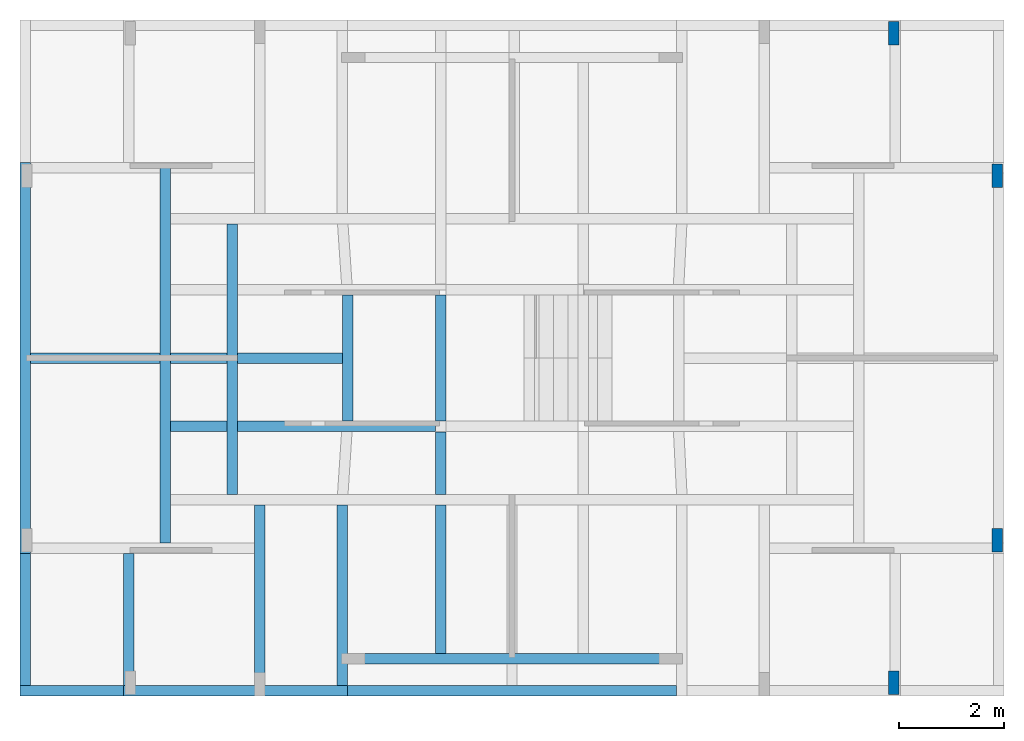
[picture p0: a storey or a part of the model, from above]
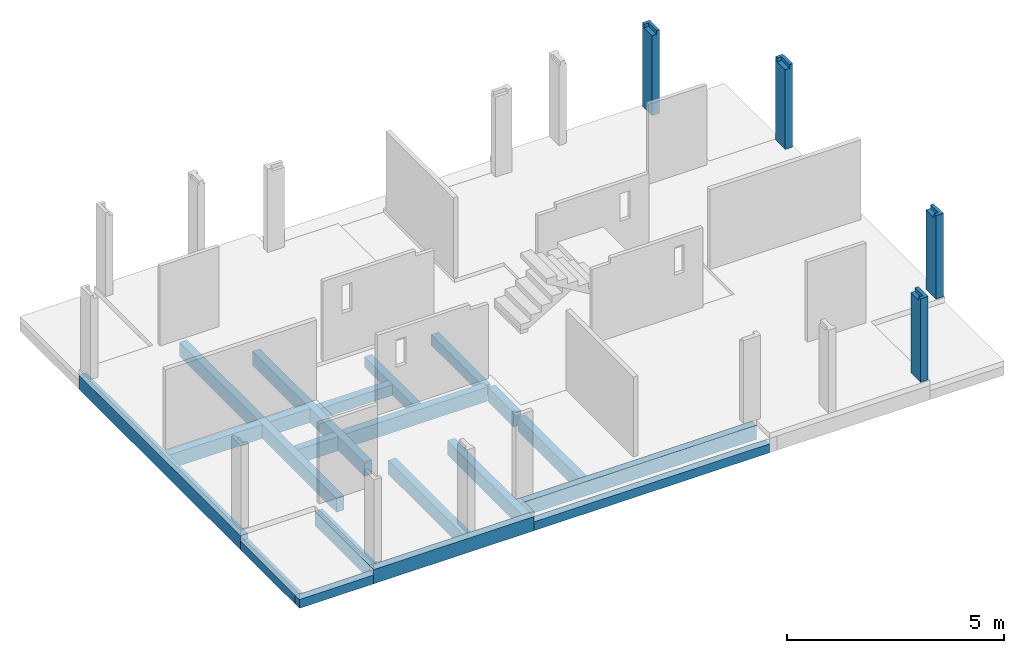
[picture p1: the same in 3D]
Properties of the parts of a building model (IFC4), part 1 of 2

# File
Description: ViewDefinition [ReferenceView_V1.2], RevitIdentifiers [VersionGUID: 9a72d792-6bb0-4d72-8437-d171d7727dd4, NumberOfSaves: 5], CoordinateReference [CoordinateBase: Shared Coordinates], ExchangeRequirement [Structural]
Time: 2024-11-18T11:33:26-05:00
Written by: ODA SDAI 22.12
Made in: 23.1.40.56 - Exporter 23.2.5.0 - Alternate UI 23.2.5.0

# IfcProject
LongName: Las nubes conjunto residencial; Phase: Project Status

# IfcSite, Default
RefLatitude: 42, 21, 31, 181945; RefLongitude: -71, -3, -24, -263305; RefElevation: 0 m
Pset_SiteCommon - Reference: Project Information

# IfcBuilding, Las nubes
LongName: Las nubes
Pset_BuildingCommon - Reference: Project Information; NumberOfStoreys: 7
Pset_BuildingElementProxyCommon - Reference: Project Information; IsExternal: no
Pset_BuildingStoreyCommon - Reference: Project Information; sets with these values: 2

# IfcBuildingStorey: Level:NIVEL SOIC (7)
In: Las nubes
Pset_BuildingStoreyCommon - Reference: NIVEL SOIC
Name | LongName | Elevation (m)
CIMENTACIÓN | CIMENTACIÓN | -3.52235e-13
PISO 2 | PISO 2 | 2.35
PISO 3 | PISO 3 | 4.7
PISO 4 | PISO 4 | 7.05
PISO 5 | PISO 5 | 9.4
PISO 6 | PISO 6 | 11.75
CUBIERTA | CUBIERTA | 14.1

# IfcBeam: AUS-C Purlin:CR-1 (50)
Type - PredefinedType: BEAM; Material: Steel - 300+
Type - Pset_BeamCommon - IsExternal: no; LoadBearing: yes
Classification: 21.02.10.20.10 Uniformat (Uniformat)
Pset_BeamCommon - Slope: 0 deg; Roll: 0 deg; Reference: CR-1
Pset_EnvironmentalImpactIndicators - Reference: CR-1; sets with these values: 2
Qto_BeamBaseQuantities - CrossSectionArea: 0.000612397 m2
Name (AUS-C Purlin:CR-1:...) | In | Span (m) = Length (m) | OuterSurfaceArea (m2) | GrossSurfaceArea (m2) = NetSurfaceArea (m2) | GrossVolume (m3) | NetVolume (m3)
990080 | CUBIERTA | 2.52 | 1.39448 | 1.39571 | 0.0013854 | 0.00138543
990338 | CUBIERTA | 2.52 | 1.39463 | 1.39586 | 0.00138555 | 0.00138557
990475 | CUBIERTA | 1.6 | 0.89842 | 0.899645 | 0.000892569 | 0.000892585
990761 | CUBIERTA | 1.6 | 0.89842 | 0.899645 | 0.000892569 | 0.000892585
991150 | CUBIERTA | 2.52 | 1.49099 | 1.49221 | 0.00148128 | 0.0014813
991410 | CUBIERTA | 1.6 | 0.924611 | 0.925836 | 0.000918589 | 0.000918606
991456 | CUBIERTA | 3.2125 | 1.91694 | 1.91816 | 0.00190445 | 0.00190449
991547 | CUBIERTA | 3.2125 | 1.91694 | 1.91817 | 0.00190446 | 0.00190449
991572 | CUBIERTA | 2.08 | 1.25547 | 1.2567 | 0.0012473 | 0.00124732
991665 | CUBIERTA | 2.04 | 1.23047 | 1.2317 | 0.00122246 | 0.00122248
993671 | CUBIERTA | 2.695 | 1.59871 | 1.59993 | 0.0015883 | 0.00158833
993950 | CUBIERTA | 2.2375 | 1.3167 | 1.31792 | 0.00130812 | 0.00130815
994002 | CUBIERTA | 2.695 | 1.59886 | 1.60008 | 0.00158844 | 0.00158847
994153 | CUBIERTA | 1.32 | 0.741837 | 0.743061 | 0.000737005 | 0.000737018
994368 | CUBIERTA | 2.695 | 1.6343 | 1.63553 | 0.00162366 | 0.00162369
994370 | CUBIERTA | 1.32 | 0.77728 | 0.778505 | 0.000772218 | 0.000772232
994432 | CUBIERTA | 2.52 | 1.39126 | 1.39249 | 0.0013822 | 0.00138223
994434 | CUBIERTA | 2.52 | 1.39463 | 1.39586 | 0.00138555 | 0.00138557
994436 | CUBIERTA | 1.6 | 0.89842 | 0.899645 | 0.000892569 | 0.000892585
994438 | CUBIERTA | 1.6 | 0.89842 | 0.899645 | 0.000892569 | 0.000892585
994440 | CUBIERTA | 2.52 | 1.49099 | 1.49221 | 0.00148128 | 0.0014813
994442 | CUBIERTA | 1.6 | 0.924611 | 0.925836 | 0.000918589 | 0.000918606
994444 | CUBIERTA | 3.2125 | 1.91694 | 1.91816 | 0.00190445 | 0.00190449
994446 | CUBIERTA | 3.2125 | 1.91694 | 1.91817 | 0.00190446 | 0.00190449
994448 | CUBIERTA | 1.6 | 0.924153 | 0.925378 | 0.000918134 | 0.000918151
994450 | CUBIERTA | 2.52 | 1.48768 | 1.48891 | 0.001478 | 0.00147802
994452 | CUBIERTA | 2.695 | 1.59871 | 1.59993 | 0.0015883 | 0.00158833
994454 | CUBIERTA | 2.695 | 1.59871 | 1.59993 | 0.0015883 | 0.00158833
994456 | CUBIERTA | 2.695 | 1.59886 | 1.60008 | 0.00158844 | 0.00158847
994458 | CUBIERTA | 1.32 | 0.741837 | 0.743061 | 0.000737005 | 0.000737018
994460 | CUBIERTA | 2.695 | 1.59886 | 1.60008 | 0.00158844 | 0.00158847
994462 | CUBIERTA | 1.32 | 0.741837 | 0.743061 | 0.000737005 | 0.000737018
1430801 | PISO 2 | 2.08 | 1.25473 | 1.25596 | 0.00124656 | 0.00124658
1430803 | PISO 2 | 3.2125 | 1.91427 | 1.91549 | 0.0019018 | 0.00190183
1430807 | PISO 2 | 2.56 | 1.506 | 1.50722 | 0.00149619 | 0.00149622
1430809 | PISO 2 | 2.635 | 1.54966 | 1.55088 | 0.00153956 | 0.00153959
1430811 | PISO 2 | 2.56 | 1.50504 | 1.50626 | 0.00149524 | 0.00149526
1430813 | PISO 2 | 1.415 | 0.798852 | 0.800077 | 0.000793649 | 0.000793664
1430820 | PISO 2 | 2.56 | 1.50599 | 1.50722 | 0.00149619 | 0.00149621
1430822 | PISO 2 | 2.635 | 1.55007 | 1.55129 | 0.00153997 | 0.00154
1430824 | PISO 2 | 2.56 | 1.50605 | 1.50727 | 0.00149624 | 0.00149626
1430826 | PISO 2 | 1.415 | 0.799666 | 0.800891 | 0.000794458 | 0.000794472
1430828 | PISO 2 | 1.6 | 0.923341 | 0.924565 | 0.000917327 | 0.000917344
1430830 | PISO 2 | 3.2125 | 1.91561 | 1.91683 | 0.00190313 | 0.00190317
1430839 | PISO 2 | 1.415 | 0.799702 | 0.800927 | 0.000794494 | 0.000794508
1430841 | PISO 2 | 1.415 | 0.799699 | 0.800924 | 0.000794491 | 0.000794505
1430843 | PISO 2 | 1.6 | 0.924607 | 0.925832 | 0.000918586 | 0.000918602
1430845 | PISO 2 | 3.2125 | 1.91636 | 1.91759 | 0.00190388 | 0.00190392
1430849 | PISO 2 | 1.6 | 0.924267 | 0.925491 | 0.000918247 | 0.000918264
1430851 | PISO 2 | 3.2125 | 1.91629 | 1.91751 | 0.00190381 | 0.00190384

# IfcBeam: M_Concrete-Rectangular Beam:(0.085x0.10) (9)
Type - PredefinedType: BEAM; Material: Concrete - Cast-in-Place Concrete - 28 MPa SLAB
Type - Pset_BeamCommon - IsExternal: no; LoadBearing: yes
Classification: 21.02.10.10.20 Uniformat (Uniformat)
Pset_BeamCommon - Slope: 0 deg; Roll: 0 deg; Reference: (0.085x0.10)
Pset_EnvironmentalImpactIndicators - Reference: (0.085x0.10); sets with these values: 2
Qto_BeamBaseQuantities - CrossSectionArea: 0.0085 m2
Name (M_Concrete-Rectangular Beam:(0.085x0.10):...) | In | Span (m) = Length (m) | OuterSurfaceArea (m2) | GrossSurfaceArea (m2) | NetSurfaceArea (m2) | GrossVolume (m3) | NetVolume (m3)
638217 | PISO 2 | 4.07732 | 0.570725 | 0.587725 | 1.44185 | 0.0131112 | 0.0323425
638219 | PISO 2 | 2.7575 | 0.869501 | 0.886501 | 0.886501 | 0.019975 | 0.019975
638221 | PISO 2 | 1.93233 | 0.65675 | 0.67375 | 0.67375 | 0.0150875 | 0.0150875
638223 | PISO 2 | 7.4 | 2.405 | 2.422 | 2.422 | 0.05525 | 0.05525
638227 | PISO 2 | 2.7575 | 0.869499 | 0.886499 | 0.886499 | 0.019975 | 0.019975
643864 | PISO 2 | 3.715 | 0.184999 | 0.201999 | 1.29755 | 0.00424999 | 0.0290275
706505 | PISO 2 | 4.09234 | 0.837125 | 0.854125 | 1.43167 | 0.0192312 | 0.0321087
713027 | PISO 3 | 1.93233 | 0.65675 | 0.67375 | 0.67375 | 0.0150875 | 0.0150875
713029 | PISO 3 | 7.4 | 2.405 | 2.422 | 2.422 | 0.05525 | 0.05525

# IfcBeam: M_Concrete-Rectangular Beam:(0.085x0.10) (5)
Type - PredefinedType: BEAM; Material: Concrete - Cast-in-Place Concrete - 35 MPa
Type - Pset_BeamCommon - IsExternal: no; LoadBearing: yes
Classification: 21.02.10.10.20 Uniformat (Uniformat)
Pset_BeamCommon - Slope: 0 deg; Roll: 0 deg; Reference: (0.085x0.10)
Pset_EnvironmentalImpactIndicators - Reference: (0.085x0.10); sets with these values: 2
Qto_BeamBaseQuantities - CrossSectionArea: 0.0085 m2
Name (M_Concrete-Rectangular Beam:(0.085x0.10):...) | In | Span (m) = Length (m) | OuterSurfaceArea (m2) | GrossSurfaceArea (m2) = NetSurfaceArea (m2) | GrossVolume (m3) = NetVolume (m3)
713233 | PISO 3 | 1.9323 | 0.65675 | 0.67375 | 0.0150875
719450 | PISO 6 | 2.7575 | 0.869501 | 0.886501 | 0.019975
719454 | PISO 6 | 7.4 | 2.405 | 2.422 | 0.05525
1321130 | CUBIERTA | 7.34499 | 2.7491 | 2.7661 | 0.063155
1321282 | CUBIERTA | 4.15 | 1.5355 | 1.5525 | 0.035275

# IfcBeam: M_Concrete-Rectangular Beam:(0.085x0.10) (95)
Type - PredefinedType: BEAM; Material: Concrete, Cast In Situ
Type - Pset_BeamCommon - IsExternal: no; LoadBearing: yes
Classification: 21.02.10.10.20 Uniformat (Uniformat)
Pset_BeamCommon - Slope: 0 deg; Roll: 0 deg; Reference: (0.085x0.10)
Pset_EnvironmentalImpactIndicators - Reference: (0.085x0.10); sets with these values: 2
Qto_BeamBaseQuantities - CrossSectionArea: 0.0085 m2
Name (M_Concrete-Rectangular Beam:(0.085x0.10):...) | In | Span (m) = Length (m) | OuterSurfaceArea (m2) | GrossSurfaceArea (m2) | NetSurfaceArea (m2) | GrossVolume (m3) | NetVolume (m3)
636093 | PISO 2 | 2.75751 | 0.869502 | 0.886502 | 0.886502 | 0.019975 | 0.019975
636519 | PISO 2 | 1.93231 | 0.65675 | 0.67375 | 0.67375 | 0.0150875 | 0.0150875
636549 | PISO 2 | 7.4 | 2.405 | 2.422 | 2.422 | 0.05525 | 0.05525
636627 | PISO 2 | 2.7575 | 0.8695 | 0.8865 | 0.8865 | 0.019975 | 0.019975
643637 | PISO 2 | 3.715 | 0.21645 | 0.23345 | 1.329 | 0.0049725 | 0.02975
705643 | PISO 2 | 1.9323 | 0.65675 | 0.67375 | 0.67375 | 0.0150875 | 0.0150875
706673 | PISO 2 | 4.09233 | 0.837125 | 0.854125 | 1.4104 | 0.0192312 | 0.03162
707792 | PISO 2 | 1.93204 | 0.65675 | 0.67375 | 0.67375 | 0.0150875 | 0.0150875
709677 | PISO 2 | 4.07731 | 0.539275 | 0.556275 | 1.4104 | 0.0123887 | 0.03162
713015 | PISO 3 | 2.75751 | 0.869502 | 0.886502 | 0.886502 | 0.019975 | 0.019975
713017 | PISO 3 | 1.93231 | 0.65675 | 0.67375 | 0.67375 | 0.0150875 | 0.0150875
713019 | PISO 3 | 7.4 | 2.405 | 2.422 | 2.422 | 0.05525 | 0.05525
713021 | PISO 3 | 2.7575 | 0.8695 | 0.8865 | 0.8865 | 0.019975 | 0.019975
713023 | PISO 3 | 4.07732 | 0.570725 | 0.587725 | 1.44185 | 0.0131112 | 0.0323425
713025 | PISO 3 | 2.7575 | 0.869501 | 0.886501 | 0.886501 | 0.019975 | 0.019975
713031 | PISO 3 | 2.7575 | 0.869499 | 0.886499 | 0.886499 | 0.019975 | 0.019975
713073 | PISO 3 | 3.715 | 0.21645 | 0.23345 | 1.329 | 0.0049725 | 0.02975
713075 | PISO 3 | 3.715 | 1.07855 | 1.09555 | 1.29755 | 0.0247775 | 0.0290275
713235 | PISO 3 | 4.07734 | 0.837125 | 0.854125 | 1.44185 | 0.0192312 | 0.0323425
713237 | PISO 3 | 3.715 | 0.185 | 0.202 | 1.29755 | 0.00425 | 0.0290275
713239 | PISO 3 | 4.07733 | 0.837125 | 0.854125 | 1.44185 | 0.0192312 | 0.0323425
713241 | PISO 3 | 3.71502 | 1.07855 | 1.09555 | 1.29756 | 0.0247775 | 0.0290277
713243 | PISO 3 | 1.93204 | 0.65675 | 0.67375 | 0.67375 | 0.0150875 | 0.0150875
713247 | PISO 3 | 4.07731 | 0.539275 | 0.556275 | 1.4104 | 0.0123887 | 0.03162
718582 | PISO 4 | 2.75751 | 0.869502 | 0.886502 | 0.886502 | 0.019975 | 0.019975
718584 | PISO 4 | 1.93231 | 0.65675 | 0.67375 | 0.67375 | 0.0150875 | 0.0150875
718586 | PISO 4 | 7.4 | 2.405 | 2.422 | 2.422 | 0.05525 | 0.05525
718588 | PISO 4 | 2.7575 | 0.8695 | 0.8865 | 0.8865 | 0.019975 | 0.019975
718590 | PISO 4 | 4.07732 | 0.570725 | 0.587725 | 1.44185 | 0.0131112 | 0.0323425
718592 | PISO 4 | 2.7575 | 0.869501 | 0.886501 | 0.886501 | 0.019975 | 0.019975
718594 | PISO 4 | 1.93233 | 0.65675 | 0.67375 | 0.67375 | 0.0150875 | 0.0150875
718596 | PISO 4 | 7.4 | 2.405 | 2.422 | 2.422 | 0.05525 | 0.05525
718598 | PISO 4 | 2.7575 | 0.869499 | 0.886499 | 0.886499 | 0.019975 | 0.019975
718640 | PISO 4 | 3.715 | 0.21645 | 0.23345 | 1.329 | 0.0049725 | 0.02975
718642 | PISO 4 | 3.715 | 1.07855 | 1.09555 | 1.29755 | 0.0247775 | 0.0290275
718800 | PISO 4 | 1.9323 | 0.65675 | 0.67375 | 0.67375 | 0.0150875 | 0.0150875
718802 | PISO 4 | 4.07734 | 0.837125 | 0.854125 | 1.44185 | 0.0192312 | 0.0323425
718804 | PISO 4 | 3.715 | 0.185 | 0.202 | 1.29755 | 0.00425 | 0.0290275
718806 | PISO 4 | 4.07733 | 0.837125 | 0.854125 | 1.44185 | 0.0192312 | 0.0323425
718808 | PISO 4 | 3.71502 | 1.07855 | 1.09555 | 1.29756 | 0.0247775 | 0.0290277
718810 | PISO 4 | 1.93204 | 0.65675 | 0.67375 | 0.67375 | 0.0150875 | 0.0150875
718814 | PISO 4 | 4.07731 | 0.539275 | 0.556275 | 1.4104 | 0.0123887 | 0.03162
719023 | PISO 5 | 2.75751 | 0.869502 | 0.886502 | 0.886502 | 0.019975 | 0.019975
719025 | PISO 5 | 1.93231 | 0.65675 | 0.67375 | 0.67375 | 0.0150875 | 0.0150875
719027 | PISO 5 | 7.4 | 2.405 | 2.422 | 2.422 | 0.05525 | 0.05525
719029 | PISO 5 | 2.7575 | 0.8695 | 0.8865 | 0.8865 | 0.019975 | 0.019975
719031 | PISO 5 | 4.07732 | 0.570725 | 0.587725 | 1.44185 | 0.0131112 | 0.0323425
719033 | PISO 5 | 2.7575 | 0.869501 | 0.886501 | 0.886501 | 0.019975 | 0.019975
719035 | PISO 5 | 1.93233 | 0.65675 | 0.67375 | 0.67375 | 0.0150875 | 0.0150875
719037 | PISO 5 | 7.4 | 2.405 | 2.422 | 2.422 | 0.05525 | 0.05525
719039 | PISO 5 | 2.7575 | 0.869499 | 0.886499 | 0.886499 | 0.019975 | 0.019975
719081 | PISO 5 | 3.715 | 0.21645 | 0.23345 | 1.329 | 0.0049725 | 0.02975
719083 | PISO 5 | 3.715 | 1.07855 | 1.09555 | 1.29755 | 0.0247775 | 0.0290275
719241 | PISO 5 | 1.9323 | 0.65675 | 0.67375 | 0.67375 | 0.0150875 | 0.0150875
719243 | PISO 5 | 4.07734 | 0.837125 | 0.854125 | 1.44185 | 0.0192312 | 0.0323425
719245 | PISO 5 | 3.715 | 0.185 | 0.202 | 1.29755 | 0.00425 | 0.0290275
719247 | PISO 5 | 4.07733 | 0.837125 | 0.854125 | 1.44185 | 0.0192312 | 0.0323425
719249 | PISO 5 | 3.71502 | 1.07855 | 1.09555 | 1.29756 | 0.0247775 | 0.0290277
719251 | PISO 5 | 1.93204 | 0.65675 | 0.67375 | 0.67375 | 0.0150875 | 0.0150875
719255 | PISO 5 | 4.07731 | 0.539275 | 0.556275 | 1.4104 | 0.0123887 | 0.03162
719440 | PISO 6 | 2.75751 | 0.869502 | 0.886502 | 0.886502 | 0.019975 | 0.019975
719442 | PISO 6 | 1.93231 | 0.65675 | 0.67375 | 0.67375 | 0.0150875 | 0.0150875
719444 | PISO 6 | 7.4 | 2.405 | 2.422 | 2.422 | 0.05525 | 0.05525
719446 | PISO 6 | 2.7575 | 0.8695 | 0.8865 | 0.8865 | 0.019975 | 0.019975
719448 | PISO 6 | 4.07732 | 0.570725 | 0.587725 | 1.44185 | 0.0131112 | 0.0323425
719452 | PISO 6 | 1.93233 | 0.65675 | 0.67375 | 0.67375 | 0.0150875 | 0.0150875
719456 | PISO 6 | 2.7575 | 0.869499 | 0.886499 | 0.886499 | 0.019975 | 0.019975
719498 | PISO 6 | 3.715 | 0.21645 | 0.23345 | 1.329 | 0.0049725 | 0.02975
719500 | PISO 6 | 3.715 | 1.07855 | 1.09555 | 1.29755 | 0.0247775 | 0.0290275
719658 | PISO 6 | 1.9323 | 0.65675 | 0.67375 | 0.67375 | 0.0150875 | 0.0150875
719660 | PISO 6 | 4.07734 | 0.837125 | 0.854125 | 1.44185 | 0.0192312 | 0.0323425
719662 | PISO 6 | 3.715 | 0.185 | 0.202 | 1.29755 | 0.00425 | 0.0290275
719664 | PISO 6 | 4.07733 | 0.837125 | 0.854125 | 1.44185 | 0.0192312 | 0.0323425
719666 | PISO 6 | 3.71502 | 1.07855 | 1.09555 | 1.29756 | 0.0247775 | 0.0290277
719668 | PISO 6 | 1.93204 | 0.65675 | 0.67375 | 0.67375 | 0.0150875 | 0.0150875
719672 | PISO 6 | 4.07731 | 0.539275 | 0.556275 | 1.4104 | 0.0123887 | 0.03162
957652 | CUBIERTA | 2.7725 | 1.04155 | 1.05855 | 1.05855 | 0.0239275 | 0.0239275
958326 | CUBIERTA | 6.395 | 2.3976 | 2.4146 | 2.4146 | 0.05508 | 0.05508
958989 | CUBIERTA | 2.7725 | 1.04155 | 1.05855 | 1.05855 | 0.0239275 | 0.0239275
959484 | CUBIERTA | 2.7725 | 1.04155 | 1.05855 | 1.05855 | 0.0239275 | 0.0239275
960133 | CUBIERTA | 2.6 | 0.962 | 0.979 | 0.979 | 0.0221 | 0.0221
1321072 | CUBIERTA | 2.7725 | 1.04155 | 1.05855 | 1.05855 | 0.0239275 | 0.0239275
1321202 | CUBIERTA | 1.975 | 0.715025 | 0.732025 | 0.732025 | 0.0164262 | 0.0164262
1321321 | CUBIERTA | 0.732418 | 0.2331 | 0.2501 | 0.2501 | 0.005355 | 0.005355
1321380 | CUBIERTA | 6.395 | 2.36615 | 2.38315 | 2.38315 | 0.0543575 | 0.0543575
1321554 | CUBIERTA | 0.732418 | 0.2331 | 0.2501 | 0.2501 | 0.005355 | 0.005355
1321623 | CUBIERTA | 1.975 | 0.746475 | 0.763475 | 0.763475 | 0.0171487 | 0.0171487
1321714 | CUBIERTA | 7.345 | 2.71765 | 2.73465 | 2.73465 | 0.0624325 | 0.0624325
1321788 | CUBIERTA | 1.975 | 0.715025 | 0.732025 | 0.732025 | 0.0164262 | 0.0164262
1321849 | CUBIERTA | 4.15 | 1.5355 | 1.5525 | 1.5525 | 0.035275 | 0.035275
1321901 | CUBIERTA | 0.732418 | 0.20165 | 0.21865 | 0.21865 | 0.0046325 | 0.0046325
1321971 | CUBIERTA | 0.732418 | 0.2331 | 0.2501 | 0.2501 | 0.005355 | 0.005355
1322015 | CUBIERTA | 4.15 | 1.50405 | 1.52105 | 1.52105 | 0.0345525 | 0.0345525
1322057 | CUBIERTA | 1.975 | 0.715025 | 0.732025 | 0.732025 | 0.0164262 | 0.0164262
1356818 | CUBIERTA | 4.15 | 1.50405 | 1.52105 | 1.52105 | 0.0345525 | 0.0345525

# IfcBeam: M_Concrete-Rectangular Beam:(0.085x0.20) (2)
In: CUBIERTA
Type - PredefinedType: BEAM; Material: Concrete - Cast-in-Place Concrete - 35 MPa
Type - Pset_BeamCommon - IsExternal: no; LoadBearing: yes
Classification: 21.02.10.10.20 Uniformat (Uniformat)
Pset_BeamCommon - Slope: 0 deg; Roll: 0 deg; Reference: (0.085x0.20)
Pset_EnvironmentalImpactIndicators - Reference: (0.085x0.20); sets with these values: 2
Qto_BeamBaseQuantities - CrossSectionArea: 0.017 m2
Name (M_Concrete-Rectangular Beam:(0.085x0.20):...) | Span (m) = Length (m) | OuterSurfaceArea (m2) | GrossSurfaceArea (m2) | NetSurfaceArea (m2) | GrossVolume (m3) | NetVolume (m3)
814081 | 1.975 | 1.02742 | 1.06142 | 1.06142 | 0.0306425 | 0.0306425
814476 | 4.135 | 1.28962 | 1.32362 | 2.23685 | 0.0384625 | 0.064685

# IfcBeam: M_Concrete-Rectangular Beam:(0.085x0.20) (36)
Type - PredefinedType: BEAM; Material: Concrete, Cast In Situ
Type - Pset_BeamCommon - IsExternal: no; LoadBearing: yes
Classification: 21.02.10.10.20 Uniformat (Uniformat)
Pset_BeamCommon - Roll: 0 deg; Reference: (0.085x0.20)
Pset_EnvironmentalImpactIndicators - Reference: (0.085x0.20); sets with these values: 2
Name (M_Concrete-Rectangular Beam:(0.085x0.20):...) | In | Slope (deg) | Span (m) = Length (m) | CrossSectionArea (m2) | OuterSurfaceArea (m2) | GrossSurfaceArea (m2) | NetSurfaceArea (m2) | GrossVolume (m3) | NetVolume (m3)
800978 | CUBIERTA | 0 | 1.975 | 0.017 | 1.02742 | 1.06142 | 1.06142 | 0.0306425 | 0.0306425
801053 | CUBIERTA | 0 | 4.135 | 0.017 | 0.879225 | 0.913225 | 2.23685 | 0.0262225 | 0.064685
803131 | CUBIERTA | 0 | 6.395 | 0.017 | 3.1977 | 3.2317 | 3.2317 | 0.09537 | 0.09537
813651 | CUBIERTA | 0 | 1.975 | 0.017 | 1.02742 | 1.06142 | 1.06142 | 0.0306425 | 0.0306425
813653 | CUBIERTA | 0 | 4.135 | 0.017 | 1.28962 | 1.32362 | 2.23685 | 0.0384625 | 0.064685
813677 | CUBIERTA | 0 | 6.395 | 1.167 | 1.0642 | 3.3982 | 3.3982 | 0.099195 | 0.099195
814083 | CUBIERTA | 0 | 4.135 | 0.017 | 0.879225 | 0.913225 | 2.23685 | 0.0262225 | 0.064685
814107 | CUBIERTA | 0 | 6.395
814474 | CUBIERTA | 0 | 1.975 | 0.017 | 1.02742 | 1.06142 | 1.06142 | 0.0306425 | 0.0306425
945990 | CUBIERTA | 8.53077 | 3.65551 | 0.719651 | 0.660047 | 2.09935 | 2.09935 | 0.0611703 | 0.0611703
946601 | CUBIERTA | 8.53077 | 3.74596 | 1.07166 |  |  | 2.14332 |  | 0.0597846
946695 | CUBIERTA | 8.53077 | 3.78673 | 0.116124 | 0.143781 | 0.376029 | 2.10361 | 0.00987051 | 0.0600519
946936 | CUBIERTA | 0 | 4.205 | 0.77528 | 0.776781 | 2.32734 | 2.32734 | 0.0658988 | 0.0658988
949342 | CUBIERTA | 0 | 4.205 | 0.77528 | 0.776781 | 2.32734 | 2.32734 | 0.0658988 | 0.0658988
951471 | CUBIERTA | 0 | 2.09119 | 0.40016 | 0.374425 | 1.17474 | 1.17474 | 0.0340136 | 0.0340136
956316 | PISO 2 | 8.53077 | 3.76694 | 0.725925 | 0.673151 | 2.125 | 2.125 | 0.0617036 | 0.0617036
956340 | PISO 2 | 8.53077 | 3.74596 | 1.06766 |  |  | 2.13531 |  | 0.0592667
956342 | PISO 2 | 8.53077 | 2.76054 | 0.00667373 | 0.054798 | 0.0681455 | 1.42649 | 0.000567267 | 0.03998
956346 | CUBIERTA | 0 | 4.205 | 0.77528 | 0.776781 | 2.32734 | 2.32734 | 0.0658988 | 0.0658988
956348 | CUBIERTA | 0 | 4.205 | 0.77528 | 0.776781 | 2.32734 | 2.32734 | 0.0658988 | 0.0658988
956352 | CUBIERTA | 0 | 2.09119 | 0.39616 | 0.374425 | 1.16674 | 1.16674 | 0.0336736 | 0.0336736
956574 | CUBIERTA | 0 | 6.395 | 1.72196 |  |  | 3.44392 |  | 0.10158
956680 | CUBIERTA | 0 | 6.395 | 1.6274 |  |  | 3.2548 |  | 0.0939965
956881 | CUBIERTA | 0 | 2.09025 | 0.017 | 1.14142 | 1.17542 | 1.17542 | 0.0340425 | 0.0340425
956883 | CUBIERTA | 0 | 2.09119 | 0.583036 |  |  | 1.16607 |  | 0.0335309
1118927 | PISO 2 | 8.53077 | 3.78673 | 0.116124 | 0.143781 | 0.376029 | 2.10361 | 0.00987051 | 0.0600519
1121147 | PISO 2 | 8.53077 | 3.82815 | 0.116124 | 0.143781 | 0.376029 | 2.14711 | 0.00987051 | 0.0616725
1121304 | CUBIERTA | 8.53077 | 3.82815 | 0.017 | 2.18205 | 2.21605 | 2.21605 | 0.0650785 | 0.0650785
1122548 | CUBIERTA | 8.53077 | 2.80356 | 0.00667373 | 0.054798 | 0.0681455 | 1.45101 | 0.000567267 | 0.0407113
1122616 | PISO 2 | 8.53077 | 2.76054 | 0.709029 |  |  | 1.41806 |  | 0.0393766
1132265 | CUBIERTA | 8.53077 | 2.80275 | 0.712511 |  |  | 1.42502 |  | 0.0393886
1139734 | CUBIERTA | 0 | 2.5 | 0.518225 | 0.476341 | 1.51279 | 1.51279 | 0.0440491 | 0.0440491
1454018 | CUBIERTA | 0 | 0.6 | 0.017 | 0.285 | 0.319 | 0.319 | 0.0085 | 0.0085
1454145 | CUBIERTA | 0 | 0.6 | 0.017 | 0.285 | 0.319 | 0.319 | 0.0085 | 0.0085
1454246 | CUBIERTA | 0 | 0.605182 | 0.103 | 0.1241 | 0.3301 | 0.3301 | 0.008755 | 0.008755
1454248 | CUBIERTA | 0 | 0.605182 | 0.017 | 0.285 | 0.319 | 0.319 | 0.0085 | 0.0085

# IfcBeam: M_Concrete-Rectangular Beam:(0.085x0.25), M_Concrete-Rectangular Beam:(0.085x0.25):719057
In: PISO 5
Type - PredefinedType: BEAM; Material: Concrete - Cast-in-Place Concrete - 35 MPa
Type - Pset_BeamCommon - IsExternal: no; LoadBearing: yes
Classification: 21.02.10.10.20 Uniformat (Uniformat)
Pset_BeamCommon - Slope: 0 deg; Roll: 0 deg; Reference: (0.085x0.25); Span: 6.395 m
Pset_EnvironmentalImpactIndicators - Reference: (0.085x0.25); sets with these values: 2
Qto_BeamBaseQuantities - Length: 6.395 m; CrossSectionArea: 0.02125 m2; OuterSurfaceArea: 3.7587 m2; GrossSurfaceArea: 3.8012 m2; NetSurfaceArea: 3.8012 m2; GrossVolume: 0.119213 m3; NetVolume: 0.119213 m3

# IfcBeam: M_Concrete-Rectangular Beam:(0.085x0.25) (14)
Type - PredefinedType: BEAM; Material: Concrete, Cast In Situ
Type - Pset_BeamCommon - IsExternal: no; LoadBearing: yes
Classification: 21.02.10.10.20 Uniformat (Uniformat)
Pset_BeamCommon - Slope: 0 deg; Roll: 0 deg; Reference: (0.085x0.25)
Pset_EnvironmentalImpactIndicators - Reference: (0.085x0.25); sets with these values: 2
Name (M_Concrete-Rectangular Beam:(0.085x0.25):...) | In | Span (m) = Length (m) | CrossSectionArea (m2) | OuterSurfaceArea (m2) | GrossSurfaceArea (m2) | NetSurfaceArea (m2) | GrossVolume (m3) | NetVolume (m3)
634146 | PISO 2 | 6.395 | 0.02125 | 3.7587 | 3.8012 | 3.8012 | 0.119213 | 0.119213
638907 | PISO 2 | 5.315 | 0.01105 | 1.032 | 1.0541 | 2.8811 | 0.02652 | 0.08177
639985 | PISO 2 | 6.395 | 0.02125 | 3.7587 | 3.8012 | 3.8012 | 0.119213 | 0.119213
713009 | PISO 3 | 6.395 | 0.02125 | 3.7587 | 3.8012 | 3.8012 | 0.119213 | 0.119213
713033 | PISO 3 | 5.315 | 0.01105 | 1.032 | 1.0541 | 2.8811 | 0.02652 | 0.08177
713049 | PISO 3 | 6.395 | 0.02125 | 3.7587 | 3.8012 | 3.8012 | 0.119213 | 0.119213
718576 | PISO 4 | 6.395 | 0.02125 | 3.7587 | 3.8012 | 3.8012 | 0.119213 | 0.119213
718600 | PISO 4 | 5.315 | 0.01105 | 1.032 | 1.0541 | 2.8811 | 0.02652 | 0.08177
718616 | PISO 4 | 6.395 | 0.02125 | 3.7587 | 3.8012 | 3.8012 | 0.119213 | 0.119213
719017 | PISO 5 | 6.395 | 0.02125 | 3.7587 | 3.8012 | 3.8012 | 0.119213 | 0.119213
719041 | PISO 5 | 5.315 | 0.01105 | 1.032 | 1.0541 | 2.8811 | 0.02652 | 0.08177
719434 | PISO 6 | 6.395 | 0.02125 | 3.7587 | 3.8012 | 3.8012 | 0.119213 | 0.119213
719458 | PISO 6 | 5.315 | 0.01105 | 1.032 | 1.0541 | 2.8811 | 0.02652 | 0.08177
719474 | PISO 6 | 6.395 | 0.02125 | 3.7587 | 3.8012 | 3.8012 | 0.119213 | 0.119213

# IfcBeam: M_Concrete-Rectangular Beam:(0.10x0.20) (7)
In: CUBIERTA
Type - PredefinedType: BEAM; Material: Concrete - Cast-in-Place Concrete - 28 MPa SLAB
Type - Pset_BeamCommon - IsExternal: no; LoadBearing: yes
Classification: 21.02.10.20.10 Uniformat (Uniformat)
Pset_BeamCommon - Slope: 0 deg; Roll: 0 deg; Reference: (0.10x0.20)
Pset_EnvironmentalImpactIndicators - Reference: (0.10x0.20); sets with these values: 2
Name (M_Concrete-Rectangular Beam:(0.10x0.20):...) | Span (m) = Length (m) | CrossSectionArea (m2) | OuterSurfaceArea (m2) | GrossSurfaceArea (m2) | NetSurfaceArea (m2) | GrossVolume (m3) | NetVolume (m3)
954072 | 2.535 | 0.02 | 1.521 | 1.561 | 1.561 | 0.0507 | 0.0507
956354 | 3.99 | 1.20393 |  |  | 2.40787 |  | 0.0786663
956358 | 2.535 | 0.02 | 1.521 | 1.561 | 1.561 | 0.0507 | 0.0507
957039 | 2.535 | 0.02 | 1.521 | 1.561 | 1.561 | 0.0507 | 0.0507
964649 | 3.99 | 0.02 | 2.3685 | 2.4085 | 2.4085 | 0.07895 | 0.07895
1322691 | 2.115 | 0.02 | 1.269 | 1.309 | 1.309 | 0.0423 | 0.0423
1323513 | 2.115 | 0.02 | 1.2345 | 1.2745 | 1.2745 | 0.04115 | 0.04115

# IfcBeam: M_Concrete-Rectangular Beam:(0.10x0.20), M_Concrete-Rectangular Beam:(0.10x0.20):957041
In: CUBIERTA
Type - PredefinedType: BEAM; Material: Concrete - Cast-in-Place Concrete - 35 MPa
Type - Pset_BeamCommon - IsExternal: no; LoadBearing: yes
Classification: 21.02.10.20.10 Uniformat (Uniformat)
Pset_BeamCommon - Slope: 0 deg; Roll: 0 deg; Reference: (0.10x0.20); Span: 2.535 m
Pset_EnvironmentalImpactIndicators - Reference: (0.10x0.20); sets with these values: 2
Qto_BeamBaseQuantities - Length: 2.535 m; CrossSectionArea: 0.779865 m2; NetSurfaceArea: 1.55973 m2; NetVolume: 0.0502393 m3

# IfcBeam: M_Concrete-Rectangular Beam:(0.10x0.25) (10)
Type - PredefinedType: BEAM; Material: Concrete - Cast-in-Place Concrete - 35 MPa
Type - Pset_BeamCommon - IsExternal: no; LoadBearing: yes
Classification: 21.02.10.10.10 Uniformat (Uniformat)
Pset_BeamCommon - Slope: 0 deg; Roll: 0 deg; Reference: (0.10x0.25)
Pset_EnvironmentalImpactIndicators - Reference: (0.10x0.25); sets with these values: 2
Name (M_Concrete-Rectangular Beam:(0.10x0.25):...) | In | Span (m) = Length (m) | CrossSectionArea (m2) | OuterSurfaceArea (m2) | GrossSurfaceArea (m2) = NetSurfaceArea (m2) | GrossVolume (m3) = NetVolume (m3)
634748 | PISO 2 | 3.74552 | 0.025 | 2.62187 | 2.67187 | 0.0936381
635515 | PISO 2 | 3.75 | 0.025 | 2.625 | 2.675 | 0.09375
713011 | PISO 3 | 3.76 | 0.8635 | 0.802 | 2.529 | 0.08635
713013 | PISO 3 | 3.76 | 0.8635 | 0.802 | 2.529 | 0.08635
718578 | PISO 4 | 3.76 | 0.8615 | 0.798 | 2.521 | 0.08615
718580 | PISO 4 | 3.75 | 0.8615 | 0.798 | 2.521 | 0.08615
719019 | PISO 5 | 3.76 | 0.8635 | 0.802 | 2.529 | 0.08635
719021 | PISO 5 | 3.76 | 0.8635 | 0.802 | 2.529 | 0.08635
719436 | PISO 6 | 3.76 | 0.8635 | 0.802 | 2.529 | 0.08635
719438 | PISO 6 | 3.76 | 0.8635 | 0.802 | 2.529 | 0.08635

# IfcBeam: M_Concrete-Rectangular Beam:(0.10x0.36) (2)
In: CUBIERTA
Type - PredefinedType: BEAM; Material: Concrete - Cast-in-Place Concrete - 28 MPa SLAB
Type - Pset_BeamCommon - IsExternal: no; LoadBearing: yes
Classification: 21.02.10.20.10 Uniformat (Uniformat)
Pset_BeamCommon - Slope: 0 deg; Roll: 0 deg; Reference: (0.10x0.36); Span: 4.48 m
Pset_EnvironmentalImpactIndicators - Reference: (0.10x0.36); sets with these values: 2
Qto_BeamBaseQuantities - Length: 4.48 m
Name (M_Concrete-Rectangular Beam:(0.10x0.36):...) | CrossSectionArea (m2) | NetSurfaceArea (m2) | NetVolume (m3)
1322677 | 2.14211 | 4.28422 | 0.161989
1323502 | 2.14254 | 4.28508 | 0.162167

# IfcBeam: M_Concrete-Rectangular Beam:(0.115x0.10), M_Concrete-Rectangular Beam:(0.115x0.10):641184
In: PISO 2
Type - PredefinedType: BEAM; Material: Concrete - Cast-in-Place Concrete - 28 MPa SLAB
Type - Pset_BeamCommon - IsExternal: no; LoadBearing: yes
Classification: 21.02.10.10.10 Uniformat (Uniformat)
Pset_BeamCommon - Slope: 0 deg; Roll: 0 deg; Reference: (0.115x0.10); Span: 1.8 m
Pset_EnvironmentalImpactIndicators - Reference: (0.115x0.10); sets with these values: 2
Qto_BeamBaseQuantities - Length: 1.8 m; CrossSectionArea: 0.0115 m2; OuterSurfaceArea: 0.72455 m2; GrossSurfaceArea: 0.74755 m2; NetSurfaceArea: 0.74755 m2; GrossVolume: 0.0193775 m3; NetVolume: 0.0193775 m3

# IfcBeam: M_Concrete-Rectangular Beam:(0.115x0.10) (73)
Type - PredefinedType: BEAM; Material: Concrete, Cast In Situ
Type - Pset_BeamCommon - IsExternal: no; LoadBearing: yes
Classification: 21.02.10.10.10 Uniformat (Uniformat)
Pset_BeamCommon - Slope: 0 deg; Roll: 0 deg; Reference: (0.115x0.10)
Pset_EnvironmentalImpactIndicators - Reference: (0.115x0.10); sets with these values: 2
Name (M_Concrete-Rectangular Beam:(0.115x0.10):...) | In | Span (m) = Length (m) | CrossSectionArea (m2) | OuterSurfaceArea (m2) | GrossSurfaceArea (m2) | NetSurfaceArea (m2) | GrossVolume (m3) | NetVolume (m3)
640094 | PISO 2 | 7.33 | 0.0115 | 3.1949 | 3.2179 | 3.2179 | 0.085445 | 0.085445
640390 | PISO 2 | 3.67211 | 0.0115 | 1.4104 | 1.4334 | 1.4334 | 0.03772 | 0.03772
640787 | PISO 2 | 5.315 | 0.0115 | 2.236 | 2.259 | 2.259 | 0.0598 | 0.0598
640942 | PISO 2 | 3.67232 | 0.0115 | 1.4104 | 1.4334 | 1.4334 | 0.03772 | 0.03772
641061 | PISO 2 | 1.8 | 0.0115 | 0.72455 | 0.74755 | 0.74755 | 0.0193775 | 0.0193775
641101 | PISO 2 | 1.8 | 0.0115 | 0.72455 | 0.74755 | 0.74755 | 0.0193775 | 0.0193775
641176 | PISO 2 | 7.33 | 0.0115 | 3.1949 | 3.2179 | 3.2179 | 0.085445 | 0.085445
641180 | PISO 2 | 5.315 | 0.0115 | 2.236 | 2.259 | 2.259 | 0.0598 | 0.0598
641186 | PISO 2 | 1.8 | 0.0115 | 0.72455 | 0.74755 | 0.74755 | 0.0193775 | 0.0193775
705060 | PISO 2 | 3.67228 | 0.0115 | 1.4104 | 1.4334 | 1.4334 | 0.03772 | 0.03772
706577 | PISO 2 | 3.67234 | 0.0115 | 1.25345 | 1.27645 | 1.51438 | 0.0335225 | 0.0392706
706778 | PISO 2 | 3.71502 | 0.0115 | 0.251559 | 0.274559 | 1.55101 | 0.00672774 | 0.0402502
709198 | PISO 2 | 3.6723 | 0.0115 | 1.4104 | 1.4334 | 1.4334 | 0.03772 | 0.03772
713051 | PISO 3 | 7.33 | 0.0115 | 3.1949 | 3.2179 | 3.2179 | 0.085445 | 0.085445
713053 | PISO 3 | 3.67211 | 0.0115 | 1.45985 | 1.48285 | 1.48285 | 0.0390425 | 0.0390425
713055 | PISO 3 | 5.315 | 0.0115 | 2.236 | 2.259 | 2.259 | 0.0598 | 0.0598
713057 | PISO 3 | 3.67232 | 0.0115 | 1.4104 | 1.4334 | 1.4334 | 0.03772 | 0.03772
713059 | PISO 3 | 1.8 | 0.0115 | 0.72455 | 0.74755 | 0.74755 | 0.0193775 | 0.0193775
713061 | PISO 3 | 1.8 | 0.0115 | 0.72455 | 0.74755 | 0.74755 | 0.0193775 | 0.0193775
713063 | PISO 3 | 7.33 | 0.0115 | 3.1949 | 3.2179 | 3.2179 | 0.085445 | 0.085445
713065 | PISO 3 | 5.315 | 0.0115 | 2.236 | 2.259 | 2.259 | 0.0598 | 0.0598
713067 | PISO 3 | 1.8 | 0.0115 | 0.72455 | 0.74755 | 0.74755 | 0.0193775 | 0.0193775
713069 | PISO 3 | 1.8 | 0.0115 | 0.72455 | 0.74755 | 0.74755 | 0.0193775 | 0.0193775
713231 | PISO 3 | 3.67228 | 0.0115 | 1.4104 | 1.4334 | 1.4334 | 0.03772 | 0.03772
713245 | PISO 3 | 3.6723 | 0.0115 | 1.4104 | 1.4334 | 1.4334 | 0.03772 | 0.03772
718618 | PISO 4 | 7.33 | 0.0115 | 3.1949 | 3.2179 | 3.2179 | 0.085445 | 0.085445
718620 | PISO 4 | 3.67211 | 0.0115 | 1.45985 | 1.48285 | 1.48285 | 0.0390425 | 0.0390425
718622 | PISO 4 | 5.315 | 0.0115 | 2.236 | 2.259 | 2.259 | 0.0598 | 0.0598
718624 | PISO 4 | 3.67232 | 0.0115 | 1.4104 | 1.4334 | 1.4334 | 0.03772 | 0.03772
718626 | PISO 4 | 1.8 | 0.0115 | 0.72455 | 0.74755 | 0.74755 | 0.0193775 | 0.0193775
718628 | PISO 4 | 1.8 | 0.0115 | 0.72455 | 0.74755 | 0.74755 | 0.0193775 | 0.0193775
718630 | PISO 4 | 7.33 | 0.0115 | 3.1949 | 3.2179 | 3.2179 | 0.085445 | 0.085445
718632 | PISO 4 | 5.315 | 0.0115 | 2.236 | 2.259 | 2.259 | 0.0598 | 0.0598
718634 | PISO 4 | 1.8
718636 | PISO 4 | 1.8 | 0.0115 | 0.72455 | 0.74755 | 0.74755 | 0.0193775 | 0.0193775
718798 | PISO 4 | 3.67228 | 0.0115 | 1.4104 | 1.4334 | 1.4334 | 0.03772 | 0.03772
718812 | PISO 4 | 3.6723 | 0.0115 | 1.4104 | 1.4334 | 1.4334 | 0.03772 | 0.03772
719059 | PISO 5 | 7.33 | 0.0115 | 3.1949 | 3.2179 | 3.2179 | 0.085445 | 0.085445
719061 | PISO 5 | 3.67211 | 0.0115 | 1.4104 | 1.4334 | 1.4334 | 0.03772 | 0.03772
719063 | PISO 5 | 5.315 | 0.0115 | 2.236 | 2.259 | 2.259 | 0.0598 | 0.0598
719065 | PISO 5 | 3.67232 | 0.0115 | 1.4104 | 1.4334 | 1.4334 | 0.03772 | 0.03772
719067 | PISO 5 | 1.8 | 0.0115 | 0.72455 | 0.74755 | 0.74755 | 0.0193775 | 0.0193775
719069 | PISO 5 | 1.8 | 0.0115 | 0.72455 | 0.74755 | 0.74755 | 0.0193775 | 0.0193775
719071 | PISO 5 | 7.33 | 0.0115 | 3.1949 | 3.2179 | 3.2179 | 0.085445 | 0.085445
719073 | PISO 5 | 5.315 | 0.0115 | 2.236 | 2.259 | 2.259 | 0.0598 | 0.0598
719075 | PISO 5 | 1.8 | 0.0115 | 0.72455 | 0.74755 | 0.74755 | 0.0193775 | 0.0193775
719077 | PISO 5 | 1.8 | 0.0115 | 0.72455 | 0.74755 | 0.74755 | 0.0193775 | 0.0193775
719239 | PISO 5 | 3.67228 | 0.0115 | 1.4104 | 1.4334 | 1.4334 | 0.03772 | 0.03772
719253 | PISO 5 | 3.6723 | 0.0115 | 1.4104 | 1.4334 | 1.4334 | 0.03772 | 0.03772
719476 | PISO 6 | 7.33 | 0.0115 | 3.1949 | 3.2179 | 3.2179 | 0.085445 | 0.085445
719478 | PISO 6 | 3.67211 | 0.0115 | 1.4104 | 1.4334 | 1.4334 | 0.03772 | 0.03772
719480 | PISO 6 | 5.315 | 0.0115 | 2.236 | 2.259 | 2.259 | 0.0598 | 0.0598
719482 | PISO 6 | 3.67232 | 0.0115 | 1.4104 | 1.4334 | 1.4334 | 0.03772 | 0.03772
719484 | PISO 6 | 1.8 | 0.0115 | 0.72455 | 0.74755 | 0.74755 | 0.0193775 | 0.0193775
719486 | PISO 6 | 1.8 | 0.0115 | 0.72455 | 0.74755 | 0.74755 | 0.0193775 | 0.0193775
719488 | PISO 6 | 7.33 | 0.0115 | 3.1949 | 3.2179 | 3.2179 | 0.085445 | 0.085445
719490 | PISO 6 | 5.315 | 0.0115 | 2.236 | 2.259 | 2.259 | 0.0598 | 0.0598
719492 | PISO 6 | 1.8 | 0.0115 | 0.72455 | 0.74755 | 0.74755 | 0.0193775 | 0.0193775
719494 | PISO 6 | 1.8 | 0.0115 | 0.72455 | 0.74755 | 0.74755 | 0.0193775 | 0.0193775
719656 | PISO 6 | 3.67228 | 0.0115 | 1.4104 | 1.4334 | 1.4334 | 0.03772 | 0.03772
719670 | PISO 6 | 3.6723
959648 | CUBIERTA | 2.585 | 0.0115 | 1.11155 | 1.13455 | 1.13455 | 0.0297275 | 0.0297275
960206 | CUBIERTA | 2.5425 | 0.0115 | 1.09328 | 1.11628 | 1.11628 | 0.0292388 | 0.0292388
960535 | CUBIERTA | 2.6 | 0.0115 | 1.118 | 1.141 | 1.141 | 0.0299 | 0.0299
961145 | CUBIERTA | 1.4 | 0.0115 | 0.65145 | 0.67445 | 0.67445 | 0.0174225 | 0.0174225
961513 | CUBIERTA | 1.4 | 0.0115 | 0.65145 | 0.67445 | 0.67445 | 0.0174225 | 0.0174225
986299 | CUBIERTA | 0.21 | 0.0115 | 0.04085 | 0.06385 | 0.06385 | 0.0010925 | 0.0010925
986352 | CUBIERTA | 0.21 | 0.0115 | 0.04085 | 0.06385 | 0.06385 | 0.0010925 | 0.0010925
1187083 | PISO 2 | 2.5 | 0.0115 | 1.032 | 1.055 | 1.055 | 0.0276 | 0.0276
1187086 | PISO 2 | 2.5 | 0.0115 | 1.032 | 1.055 | 1.055 | 0.0276 | 0.0276
1187089 | PISO 2 | 2.5 | 0.0115 | 1.032 | 1.055 | 1.055 | 0.0276 | 0.0276
1187092 | PISO 2 | 2.5 | 0.0115 | 1.032 | 1.055 | 1.055 | 0.0276 | 0.0276
1315655 | PISO 2 | 2.5 | 0.0115 | 1.032 | 1.055 | 1.055 | 0.0276 | 0.0276

# IfcBeam: M_Concrete-Rectangular Beam:(0.115x0.20) (25)
Type - PredefinedType: BEAM; Material: Concrete, Cast In Situ
Type - Pset_BeamCommon - IsExternal: no; LoadBearing: yes
Classification: 21.02.10.20.10 Uniformat (Uniformat)
Pset_BeamCommon - Roll: 0 deg; Reference: (0.115x0.20)
Pset_EnvironmentalImpactIndicators - Reference: (0.115x0.20); sets with these values: 2
Name (M_Concrete-Rectangular Beam:(0.115x0.20):...) | In | Span (m) = Length (m) | Slope (deg) | CrossSectionArea (m2) | OuterSurfaceArea (m2) | GrossSurfaceArea (m2) | NetSurfaceArea (m2) | GrossVolume (m3) | NetVolume (m3)
946051 | CUBIERTA | 3.21654 | 8.53077 | 0.62727 | 0.770006 | 2.02455 | 2.02455 | 0.072136 | 0.072136
946135 | CUBIERTA | 3.77173 | 8.53077 | 1.1371 |  |  | 2.2742 |  | 0.0769194
946200 | CUBIERTA | 2.19778 | 8.53077 | 0.716947 |  |  | 1.43389 |  | 0.048109
946401 | CUBIERTA | 1.39811 | 8.53077 | 0.023 | 0.880809 | 0.926809 | 0.926809 | 0.0321565 | 0.0321565
946473 | CUBIERTA | 2.19771 | 8.53077 | 0.727224 |  |  | 1.45445 |  | 0.0494277
946524 | CUBIERTA | 3.21649 | 8.53077 | 0.627262 | 0.769995 | 2.02452 | 2.02452 | 0.0721351 | 0.0721351
949988 | CUBIERTA | 13.11 | 0 | 4.17099 |  |  | 8.34197 |  | 0.299921
956318 | PISO 2 | 3.21654 | 8.53077 | 0.62727 | 0.770006 | 2.02455 | 2.02455 | 0.072136 | 0.072136
956324 | PISO 2 | 2.19778 | 8.53077 | 0.707636 |  |  | 1.41527 |  | 0.0471735
956328 | PISO 2 | 1.3651 | 8.53077 | 0.453902 |  |  | 0.907804 |  | 0.0305937
956332 | PISO 2 | 1.45625 | 8.53077 | 0.023 | 0.917439 | 0.963439 | 0.963439 | 0.0334938 | 0.0334938
956336 | PISO 2 | 2.19771 | 8.53077 | 0.708289 |  |  | 1.41658 |  | 0.0471772
956338 | PISO 2 | 3.21649 | 8.53077 | 0.627262 | 0.769995 | 2.02452 | 2.02452 | 0.0721351 | 0.0721351
956350 | CUBIERTA | 13.11 | 0 | 4.17099 |  |  | 8.34198 |  | 0.299714
956364 | PISO 2 | 1.47381 | 8.53077 | 0.27829 | 0.386865 | 0.943444 | 0.943396 | 0.0320033 | 0.0320015
961790 | CUBIERTA | 0.815 | 0 | 0.0115 | 0.35045 | 0.37345 | 0.37345 | 0.0093725 | 0.0093725
961831 | CUBIERTA | 0.8275 | 0 | 0.0115 | 0.3096 | 0.3326 | 0.3326 | 0.00828 | 0.00828
1118727 | PISO 2 | 3.78673 | 8.53077 | 1.13218 |  |  | 2.26436 |  | 0.0760245
1118782 | CUBIERTA | 3.78673 | 8.53077 | 1.13218 |  |  | 2.26436 |  | 0.0760245
1119891 | CUBIERTA | 1.38 | 8.53077 | 0.266545 | 0.365821 | 0.898911 | 0.898911 | 0.0306527 | 0.0306527
1121469 | PISO 2 | 3.78673 | 8.53077 | 1.13218 |  |  | 2.26436 |  | 0.0760245
1132887 | PISO 2 | 1.42325 | 8.53077 | 0.278288 | 0.385873 | 0.94245 | 0.94245 | 0.0320032 | 0.0320032
1133516 | PISO 2 | 1.42325 | 8.53077 | 0.278289 | 0.386178 | 0.942756 | 0.942756 | 0.0320032 | 0.0320032
1133615 | PISO 2 | 1.42325 | 8.53077 | 0.278287 | 0.385452 | 0.942025 | 0.942025 | 0.032003 | 0.032003
1139736 | CUBIERTA | 2.5 | 0 | 0.023 | 1.512 | 1.558 | 1.558 | 0.0552 | 0.0552

# IfcBeam: M_Concrete-Rectangular Beam:(0.115x0.25), M_Concrete-Rectangular Beam:(0.115x0.25):639693
In: PISO 2
Type - PredefinedType: BEAM; Material: Concrete - Cast-in-Place Concrete - 28 MPa SLAB
Type - Pset_BeamCommon - IsExternal: no; LoadBearing: yes
Classification: 21.02.10.10.10 Uniformat (Uniformat)
Pset_BeamCommon - Slope: 0 deg; Roll: 0 deg; Reference: (0.115x0.25); Span: 3.495 m
Pset_EnvironmentalImpactIndicators - Reference: (0.115x0.25); sets with these values: 2
Qto_BeamBaseQuantities - Length: 3.495 m; CrossSectionArea: 0.02875 m2; OuterSurfaceArea: 2.55135 m2; GrossSurfaceArea: 2.60885 m2; NetSurfaceArea: 2.60885 m2; GrossVolume: 0.100481 m3; NetVolume: 0.100481 m3

# IfcBeam: M_Concrete-Rectangular Beam:(0.115x0.25) (29)
Type - PredefinedType: BEAM; Material: Concrete, Cast In Situ
Type - Pset_BeamCommon - IsExternal: no; LoadBearing: yes
Classification: 21.02.10.10.10 Uniformat (Uniformat)
Pset_BeamCommon - Slope: 0 deg; Roll: 0 deg; Reference: (0.115x0.25)
Pset_EnvironmentalImpactIndicators - Reference: (0.115x0.25); sets with these values: 2
Name (M_Concrete-Rectangular Beam:(0.115x0.25):...) | In | Span (m) = Length (m) | CrossSectionArea (m2) | OuterSurfaceArea (m2) | GrossSurfaceArea (m2) | NetSurfaceArea (m2) | GrossVolume (m3) | NetVolume (m3)
638993 | PISO 2 | 3.51 | 0.02875 | 2.6353 | 2.6928 | 2.6928 | 0.103788 | 0.103788
639368 | PISO 2 | 3.51 | 0.02875 | 2.6353 | 2.6928 | 2.6928 | 0.103788 | 0.103788
639689 | PISO 2 | 1.4075 | 0.02875 | 1.03295 | 1.09045 | 1.09045 | 0.0406813 | 0.0406813
639691 | PISO 2 | 3.495 | 0.02875 | 2.6353 | 2.6928 | 2.6928 | 0.103788 | 0.103788
639801 | PISO 2 | 1.4075 | 0.02875 | 0.949 | 1.0065 | 1.0065 | 0.037375 | 0.037375
713035 | PISO 3 | 3.51 | 0.02875 | 2.6353 | 2.6928 | 2.6928 | 0.103788 | 0.103788
713037 | PISO 3 | 3.51 | 0.891 | 0.8878 | 2.6698 | 2.6698 | 0.102465 | 0.102465
713041 | PISO 3 | 1.4075 | 0.545225 |  |  | 1.09045 |  | 0.0406238
713043 | PISO 3 | 3.5 | 0.90325 | 0.88895 | 2.69545 | 2.69545 | 0.103874 | 0.103874
713045 | PISO 3 | 3.5 | 0.02875 | 2.555 | 2.6125 | 2.6125 | 0.100625 | 0.100625
713047 | PISO 3 | 1.4075 | 0.02875 | 0.949 | 1.0065 | 1.0065 | 0.037375 | 0.037375
718602 | PISO 4 | 3.51 | 0.02875 | 2.6353 | 2.6928 | 2.6928 | 0.103788 | 0.103788
718604 | PISO 4 | 3.51 | 0.891 | 0.8878 | 2.6698 | 2.6698 | 0.102465 | 0.102465
718608 | PISO 4 | 1.4075 | 0.02875 | 1.03295 | 1.09045 | 1.09045 | 0.0406813 | 0.0406813
718610 | PISO 4 | 3.495 | 0.891 | 0.8878 | 2.6698 | 2.6698 | 0.102465 | 0.102465
718612 | PISO 4 | 5.295 | 1.31225 | 1.27535 | 3.89985 | 3.89985 | 0.150909 | 0.150909
718614 | PISO 4 | 1.4075 | 0.02875 | 0.949 | 1.0065 | 1.0065 | 0.037375 | 0.037375
719043 | PISO 5 | 3.51 | 0.02875 | 2.6353 | 2.6928 | 2.6928 | 0.103788 | 0.103788
719045 | PISO 5 | 3.51 | 0.02875 | 2.6353 | 2.6928 | 2.6928 | 0.103788 | 0.103788
719049 | PISO 5 | 1.4075 | 0.545225 |  |  | 1.09045 |  | 0.0406238
719051 | PISO 5 | 3.5 | 0.90325 | 0.88895 | 2.69545 | 2.69545 | 0.103874 | 0.103874
719053 | PISO 5 | 3.5 | 0.02875 | 2.555 | 2.6125 | 2.6125 | 0.100625 | 0.100625
719055 | PISO 5 | 1.4075 | 0.02875 | 0.949 | 1.0065 | 1.0065 | 0.037375 | 0.037375
719460 | PISO 6 | 3.51 | 0.02875 | 2.6353 | 2.6928 | 2.6928 | 0.103788 | 0.103788
719462 | PISO 6 | 3.51 | 0.02875 | 2.6353 | 2.6928 | 2.6928 | 0.103788 | 0.103788
719466 | PISO 6 | 1.4075 | 0.545225 |  |  | 1.09045 |  | 0.0406238
719468 | PISO 6 | 3.5 | 0.90325 | 0.88895 | 2.69545 | 2.69545 | 0.103874 | 0.103874
719470 | PISO 6 | 3.5 | 0.02875 | 2.555 | 2.6125 | 2.6125 | 0.100625 | 0.100625
719472 | PISO 6 | 1.4075 | 0.02875 | 0.949 | 1.0065 | 1.0065 | 0.037375 | 0.037375

# IfcBeam: M_Concrete-Rectangular Beam:(0.115x0.26) (6)
Type - PredefinedType: BEAM; Material: Concrete, Cast In Situ
Type - Pset_BeamCommon - IsExternal: no; LoadBearing: yes
Classification: 21.02.10.20.10 Uniformat (Uniformat)
Pset_BeamCommon - Slope: 0 deg; Roll: 0 deg; Reference: (0.115x0.26)
Pset_EnvironmentalImpactIndicators - Reference: (0.115x0.26); sets with these values: 2
Name (M_Concrete-Rectangular Beam:(0.115x0.26):...) | In | Span (m) = Length (m) | CrossSectionArea (m2) | NetSurfaceArea (m2) | NetVolume (m3)
980087 | PISO 2 | 4.03 | 1.54907 | 3.09815 | 0.115834
980203 | PISO 2 | 4.0875 | 1.57095 | 3.14191 | 0.117563
980511 | PISO 2 | 4.0875 | 1.54178 | 3.08356 | 0.115585
980586 | PISO 2 | 4.0878 | 1.57104 | 3.14208 | 0.118686
987386 | CUBIERTA | 1.06 | 0.4274 | 0.8548 | 0.030913
987464 | CUBIERTA | 1.12 | 0.271151 | 0.859702 | 0.0311823 | Qto_BeamBaseQuantities - OuterSurfaceArea: 0.3174 m2; GrossSurfaceArea: 0.859702 m2; GrossVolume: 0.0311823 m3

# IfcBeam: M_Concrete-Rectangular Beam:(0.12x0.20) (2)
Type - PredefinedType: BEAM; Material: Concrete - Cast-in-Place Concrete - 35 MPa
Type - Pset_BeamCommon - IsExternal: no; LoadBearing: yes
Classification: 21.02.10.20.10 Uniformat (Uniformat)
Pset_BeamCommon - Roll: 0 deg; Reference: (0.12x0.20); Span: 3.14968 m; Slope: 8.53077 deg
Pset_EnvironmentalImpactIndicators - Reference: (0.12x0.20); sets with these values: 2
Qto_BeamBaseQuantities - Length: 3.14968 m; CrossSectionArea: 0.619154 m2; OuterSurfaceArea: 0.806287 m2; GrossSurfaceArea: 2.0446 m2; NetSurfaceArea: 2.0446 m2; GrossVolume: 0.0742985 m3; NetVolume: 0.0742985 m3
Name (M_Concrete-Rectangular Beam:(0.12x0.20):...) | In
946323 | CUBIERTA
956330 | PISO 2

# IfcBeam: M_Concrete-Rectangular Beam:(0.20x0.10), M_Concrete-Rectangular Beam:(0.20x0.10):877224
In: CIMENTACIÓN
Type - PredefinedType: BEAM; Material: Concrete, Cast In Situ
Type - Pset_BeamCommon - IsExternal: no; LoadBearing: yes
Classification: 21.02.10.10.20 Uniformat (Uniformat)
Pset_BeamCommon - Slope: 0 deg; Roll: 0 deg; Reference: (0.20x0.10); Span: 1.19965 m
Pset_EnvironmentalImpactIndicators - Reference: (0.20x0.10); sets with these values: 2
Qto_BeamBaseQuantities - Length: 1.19965 m; CrossSectionArea: 0.02 m2; OuterSurfaceArea: 0.719789 m2; GrossSurfaceArea: 0.759789 m2; NetSurfaceArea: 0.759789 m2; GrossVolume: 0.023993 m3; NetVolume: 0.023993 m3

# IfcBeam: M_Concrete-Rectangular Beam:(0.20x0.40) (2)
In: CIMENTACIÓN
Type - PredefinedType: BEAM; Material: Concrete - Cast-in-Place Concrete - 28 MPa SLAB
Type - Pset_BeamCommon - IsExternal: no; LoadBearing: yes
Classification: 21-01 10 10 10 Uniformat (Uniformat)
Pset_BeamCommon - Slope: 0 deg; Roll: 0 deg; Reference: (0.20x0.40)
Pset_EnvironmentalImpactIndicators - Reference: (0.20x0.40); sets with these values: 2
Qto_BeamBaseQuantities - CrossSectionArea: 0.05 m2
Name (M_Concrete-Rectangular Beam:(0.20x0.40):...) | Span (m) = Length (m) | OuterSurfaceArea (m2) | GrossSurfaceArea (m2) = NetSurfaceArea (m2) | GrossVolume (m3) = NetVolume (m3)
602523 | 1.975 | 1.7775 | 1.8775 | 0.09875
602587 | 2.715 | 2.2635 | 2.3635 | 0.12575

# IfcBeam: M_Concrete-Rectangular Beam:(0.20x0.40) (11)
In: CIMENTACIÓN
Type - PredefinedType: BEAM; Material: Concrete, Cast In Situ
Type - Pset_BeamCommon - IsExternal: no; LoadBearing: yes
Classification: 21-01 10 10 10 Uniformat (Uniformat)
Pset_BeamCommon - Slope: 0 deg; Roll: 0 deg; Reference: (0.20x0.40)
Pset_EnvironmentalImpactIndicators - Reference: (0.20x0.40); sets with these values: 2
Qto_BeamBaseQuantities - CrossSectionArea: 0.05 m2
Name (M_Concrete-Rectangular Beam:(0.20x0.40):...) | Span (m) = Length (m) | OuterSurfaceArea (m2) | GrossSurfaceArea (m2) = NetSurfaceArea (m2) | GrossVolume (m3) = NetVolume (m3)
602117 | 2.715 | 2.4435 | 2.5435 | 0.13575
602178 | 1.975 | 1.5975 | 1.6975 | 0.08875
602387 | 0.615 | 0.3735 | 0.4735 | 0.02075
602423 | 6.48 | 5.652 | 5.752 | 0.314
602487 | 0.615 | 0.3735 | 0.4735 | 0.02075
602727 | 1.975 | 1.7775 | 1.8775 | 0.09875
602762 | 2.715 | 2.2635 | 2.3635 | 0.12575
602853 | 0.615 | 0.3735 | 0.4735 | 0.02075
602926 | 6.48 | 5.652 | 5.752 | 0.314
603045 | 1.975 | 1.7775 | 1.8775 | 0.09875
603101 | 2.715 | 2.2635 | 2.3635 | 0.12575

# IfcBeam: M_Concrete-Rectangular Beam:(0.20x0.45) (11)
In: CIMENTACIÓN
Type - PredefinedType: BEAM; Material: Concrete, Cast In Situ
Type - Pset_BeamCommon - IsExternal: no; LoadBearing: yes
Classification: 21.01.10.10.10 Uniformat (Uniformat)
Pset_BeamCommon - Slope: 0 deg; Roll: 0 deg; Reference: (0.20x0.45)
Pset_EnvironmentalImpactIndicators - Reference: (0.20x0.45); sets with these values: 2
Name (M_Concrete-Rectangular Beam:(0.20x0.45):...) | Span (m) = Length (m) | CrossSectionArea (m2) | OuterSurfaceArea (m2) | GrossSurfaceArea (m2) | NetSurfaceArea (m2) | GrossVolume (m3) | NetVolume (m3)
600933 | 2.6 | 0.06 | 2.4 | 2.52 | 2.52 | 0.144 | 0.144
604216 | 2.6 | 0.06 | 2.4 | 2.52 | 2.52 | 0.144 | 0.144
872121 | 2.2 | 0.06 | 2 | 2.12 | 2.12 | 0.12 | 0.12
872538 | 2.1575 | 0.06 | 1.9575 | 2.0775 | 2.0775 | 0.11745 | 0.11745
872982 | 1.4 | 0.06 | 1.2 | 1.32 | 1.32 | 0.072 | 0.072
873531 | 2.72 | 0.796 | 1.208 | 2.8 | 2.8 | 0.1592 | 0.1592
873889 | 2.72 | 0.836 | 1.248 | 2.92 | 2.92 | 0.1672 | 0.1672
878682 | 1.4 | 0.06 | 1.2 | 1.32 | 1.32 | 0.072 | 0.072
1123215 | 2.6 | 0.06 | 2.4 | 2.52 | 2.52 | 0.144 | 0.144
1123276 | 2.6 | 1.32 |  |  | 2.64 |  | 0.148
1174175 | 2.6 | 0.06 | 2.4 | 2.52 | 2.52 | 0.144 | 0.144

# IfcBeam: M_Concrete-Rectangular Beam:(0.20x0.55) (7)
In: CIMENTACIÓN
Type - PredefinedType: BEAM; Material: Concrete - Cast-in-Place Concrete - 28 MPa SLAB
Type - Pset_BeamCommon - IsExternal: no; LoadBearing: yes
Classification: 21-02 10 10 10 Uniformat (Uniformat)
Pset_BeamCommon - Reference: (0.20x0.55); Slope: 0 deg; Roll: 0 deg
Pset_EnvironmentalImpactIndicators - Reference: (0.20x0.55); sets with these values: 2
Qto_BeamBaseQuantities - CrossSectionArea: 0.08 m2
Name (M_Concrete-Rectangular Beam:(0.20x0.55):...) | Span (m) = Length (m) | OuterSurfaceArea (m2) | GrossSurfaceArea (m2) | NetSurfaceArea (m2) | GrossVolume (m3) | NetVolume (m3)
601503 | 7.33 | 8.472 | 8.632 | 8.632 | 0.5648 | 0.5648
601568 | 7.26 | 8.472 | 8.632 | 8.632 | 0.5648 | 0.5648
601648 | 3.945 | 2.961 | 3.121 | 4.574 | 0.1974 | 0.2836
601732 | 3.6875 | 4.185 | 4.345 | 4.345 | 0.279 | 0.279
601771 | 4.4675 | 5.121 | 5.281 | 5.281 | 0.3414 | 0.3414
601814 | 2.68 | 3.018 | 3.178 | 3.178 | 0.2012 | 0.2012
873086 | 6.6125 | 7.887 | 8.047 | 8.047 | 0.5258 | 0.5258

# IfcBeam: M_Concrete-Rectangular Beam:(0.20x0.55), M_Concrete-Rectangular Beam:(0.20x0.55):601698
In: CIMENTACIÓN
Type - PredefinedType: BEAM; Material: Concrete - Cast-in-Place Concrete - 35 MPa
Type - Pset_BeamCommon - IsExternal: no; LoadBearing: yes
Classification: 21-02 10 10 10 Uniformat (Uniformat)
Pset_BeamCommon - Reference: (0.20x0.55); Slope: 0 deg; Roll: 0 deg; Span: 4.065 m
Pset_EnvironmentalImpactIndicators - Reference: (0.20x0.55); sets with these values: 2
Qto_BeamBaseQuantities - Length: 4.065 m; CrossSectionArea: 0.08 m2; OuterSurfaceArea: 5.118 m2; GrossSurfaceArea: 5.278 m2; NetSurfaceArea: 5.278 m2; GrossVolume: 0.3412 m3; NetVolume: 0.3412 m3

# IfcBeam: M_Concrete-Rectangular Beam:(0.20x0.55) (40)
In: CIMENTACIÓN
Type - PredefinedType: BEAM; Material: Concrete, Cast In Situ
Type - Pset_BeamCommon - IsExternal: no; LoadBearing: yes
Classification: 21-02 10 10 10 Uniformat (Uniformat)
Pset_BeamCommon - Reference: (0.20x0.55); Slope: 0 deg; Roll: 0 deg
Pset_EnvironmentalImpactIndicators - Reference: (0.20x0.55); sets with these values: 2
Name (M_Concrete-Rectangular Beam:(0.20x0.55):...) | Span (m) = Length (m) | CrossSectionArea (m2) | OuterSurfaceArea (m2) | GrossSurfaceArea (m2) | NetSurfaceArea (m2) | GrossVolume (m3) | NetVolume (m3)
599077 | 7.26 | 2.98396 | 3.144 | 9.11193 | 9.11193 | 0.596793 | 0.596793
599309 | 3.645 | 0.08 | 4.134 | 4.294 | 4.294 | 0.2756 | 0.2756
599397 | 4.4675 | 2.6405 |  |  | 5.281 |  | 0.341337
599501 | 4.065 | 0.08 | 5.118 | 5.278 | 5.278 | 0.3412 | 0.3412
599616 | 2.68 | 0.08 | 3.018 | 3.178 | 3.178 | 0.2012 | 0.2012
599721 | 13.225 | 0.08 | 15.63 | 15.79 | 15.79 | 1.042 | 1.042
599966 | 7.33 | 0.08 | 8.694 | 8.854 | 8.854 | 0.5796 | 0.5796
600142 | 4.4675 | 2.6775 |  |  | 5.355 |  | 0.3266
600196 | 5.2525 | 0.08 | 6.063 | 6.223 | 6.223 | 0.4042 | 0.4042
600243 | 3.6875 | 0.08 | 4.185 | 4.345 | 4.345 | 0.279 | 0.279
600328 | 2.68 | 0.08 | 3.258 | 3.418 | 3.418 | 0.2172 | 0.2172
600390 | 4.065 | 0.08 | 4.878 | 5.038 | 5.038 | 0.3252 | 0.3252
600439 | 5.3575 | 0.08 | 6.189 | 6.349 | 6.349 | 0.4126 | 0.4126
600471 | 3.945 | 0.08 | 1.293 | 1.453 | 4.574 | 0.0861999 | 0.2836
600556 | 4.43 | 0.08 | 3.396 | 3.556 | 5.14076 | 0.2264 | 0.321384
600610 | 5.2525 | 3.2115 |  |  | 6.423 |  | 0.4122
600642 | 5.2525 | 0.08 | 4.53 | 4.69 | 6.143 | 0.302 | 0.3882
600766 | 6.48 | 0.08 | 7.536 | 7.696 | 7.696 | 0.5024 | 0.5024
600821 | 3.03 | 0.08 | 3.396 | 3.556 | 3.556 | 0.2264 | 0.2264
600886 | 4.43 | 0.08 | 3.396 | 3.556 | 5.156 | 0.2264 | 0.3224
601012 | 3.645 | 0.08 | 4.374 | 4.534 | 4.534 | 0.2916 | 0.2916
601079 | 1.88 | 0.08 | 2.256 | 2.416 | 2.416 | 0.1504 | 0.1504
601124 | 3.0725 | 0.08 | 3.447 | 3.607 | 3.607 | 0.2298 | 0.2298
601165 | 5.3575 | 0.08 | 2.88 | 3.04 | 6.189 | 0.192 | 0.3806
601261 | 4.4675 | 2.7605 |  |  | 5.521 |  | 0.35733
601344 | 4.065 | 0.08 | 4.878 | 5.038 | 5.038 | 0.3252 | 0.3252
601396 | 3.645 | 0.08 | 4.134 | 4.294 | 4.294 | 0.2756 | 0.2756
601453 | 2.68 | 0.08 | 3.018 | 3.178 | 3.178 | 0.2012 | 0.2012
603462 | 3.6875 | 0.08 | 4.185 | 4.345 | 4.345 | 0.279 | 0.279
603488 | 1.40926 | 0.775468 |  |  | 1.55094 |  | 0.0927157
603588 | 1.45177 | 0.800976 |  |  | 1.60195 |  | 0.0961171
604210 | 3.645 | 0.08 | 4.134 | 4.294 | 4.294 | 0.2756 | 0.2756
604212 | 3.6875 | 0.08 | 4.185 | 4.345 | 4.345 | 0.279 | 0.279
604214 | 1.41069 | 0.776258 |  |  | 1.55252 |  | 0.0928102
604218 | 1.45312 | 0.801721 |  |  | 1.60344 |  | 0.0962065
871132 | 4.43 | 0.08 | 3.447 | 3.607 | 5.14076 | 0.2298 | 0.321384
873490 | 5.2525 | 3.1715 |  |  | 6.343 |  | 0.3962
878693 | 3.24 | 0.08 | 3.84 | 4 | 4 | 0.256 | 0.256
1123278 | 5.2525 | 0.08 | 6.063 | 6.223 | 6.223 | 0.4042 | 0.4042
1174299 | 4.43 | 0.08 | 5.06076 | 5.22076 | 5.22076 | 0.337384 | 0.337384

# IfcColumn: M_Concrete-Rectangular-Column:300 x 450mm (102)
Type - PredefinedType: COLUMN; Material: Concrete, Cast-in-Place gray
Type - Pset_ColumnCommon - IsExternal: no; LoadBearing: yes
Classification: 21-02 10 Uniformat (Uniformat)
Pset_ColumnCommon - Reference: 300 x 450mm
Pset_EnvironmentalImpactIndicators - Reference: 300 x 450mm; sets with these values: 2
Name (M_Concrete-Rectangular-Column:300 x 450mm:...) | In | CrossSectionArea (m2) | NetVolume (m3)
1451331 | CIMENTACIÓN | 1.6175 | 0.207303
1451617 | CIMENTACIÓN | 1.6175 | 0.207302
1451938 | CIMENTACIÓN | 1.6175 | 0.207303
1452124 | CIMENTACIÓN | 1.6175 | 0.208653
1452315 | CIMENTACIÓN | 1.6175 | 0.207647
1452729 | CIMENTACIÓN | 1.6175 | 0.207303
1452731 | CIMENTACIÓN | 1.6175 | 0.207303
1452733 | CIMENTACIÓN | 1.6175 | 0.208653
1452735 | CIMENTACIÓN | 1.6175 | 0.207647
1452796 | CIMENTACIÓN | 1.6175 | 0.207303
1452798 | CIMENTACIÓN | 1.6175 | 0.207303
1452800 | CIMENTACIÓN | 1.6175 | 0.208653
1452802 | CIMENTACIÓN | 1.6175 | 0.208398
1452804 | CIMENTACIÓN | 1.6175 | 0.207303
1452806 | CIMENTACIÓN | 1.6175 | 0.207303
1452808 | CIMENTACIÓN | 1.6175 | 0.208653
1452810 | CIMENTACIÓN | 1.6175 | 0.208398
1452902 | PISO 2 | 1.6175 | 0.207303
1452904 | PISO 2 | 1.6175 | 0.207302
1452908 | PISO 2 | 1.6175 | 0.207303
1452910 | PISO 2 | 1.6175 | 0.208653
1452912 | PISO 2 | 1.6175 | 0.208398
1452916 | PISO 2 | 1.6175 | 0.207303
1452918 | PISO 2 | 1.6175 | 0.207303
1452920 | PISO 2 | 1.6175 | 0.208653
1452922 | PISO 2 | 1.6175 | 0.208398
1452924 | PISO 2 | 1.6175 | 0.207303
1452926 | PISO 2 | 1.6175 | 0.207303
1452928 | PISO 2 | 1.6175 | 0.208653
1452930 | PISO 2 | 1.6175 | 0.208398
1452932 | PISO 2 | 1.6175 | 0.207303
1452934 | PISO 2 | 1.6175 | 0.207303
1452936 | PISO 2 | 1.6175 | 0.208653
1452938 | PISO 2 | 1.6175 | 0.208398
1452946 | PISO 3 | 1.6175 | 0.207303
1452948 | PISO 3 | 1.6175 | 0.207302
1452952 | PISO 3 | 1.6175 | 0.207303
1452954 | PISO 3 | 1.6175 | 0.208653
1452956 | PISO 3 | 1.6175 | 0.208398
1452960 | PISO 3 | 1.6175 | 0.207303
1452962 | PISO 3 | 1.6175 | 0.207303
1452964 | PISO 3 | 1.6175 | 0.208653
1452966 | PISO 3 | 1.6175 | 0.208398
1452968 | PISO 3 | 1.6175 | 0.207303
1452970 | PISO 3 | 1.6175 | 0.207303
1452972 | PISO 3 | 1.6175 | 0.208653
1452974 | PISO 3 | 1.6175 | 0.208398
1452976 | PISO 3 | 1.6175 | 0.207303
1452978 | PISO 3 | 1.6175 | 0.207303
1452980 | PISO 3 | 1.6175 | 0.208653
1452982 | PISO 3 | 1.6175 | 0.208398
1452990 | PISO 4 | 1.6175 | 0.207303
1452992 | PISO 4 | 1.6175 | 0.207302
1452996 | PISO 4 | 1.6175 | 0.207303
1452998 | PISO 4 | 1.6175 | 0.208653
1453000 | PISO 4 | 1.6175 | 0.208398
1453004 | PISO 4 | 1.6175 | 0.207303
1453006 | PISO 4 | 1.6175 | 0.207303
1453008 | PISO 4 | 1.6175 | 0.208653
1453010 | PISO 4 | 1.6175 | 0.208398
1453012 | PISO 4 | 1.6175 | 0.207303
1453014 | PISO 4 | 1.6175 | 0.207303
1453016 | PISO 4 | 1.6175 | 0.208653
1453018 | PISO 4 | 1.6175 | 0.208398
1453020 | PISO 4 | 1.6175 | 0.207303
1453022 | PISO 4 | 1.6175 | 0.207303
1453024 | PISO 4 | 1.6175 | 0.208653
1453026 | PISO 4 | 1.6175 | 0.208398
1453034 | PISO 5 | 1.6175 | 0.207303
1453036 | PISO 5 | 1.6175 | 0.207302
1453040 | PISO 5 | 1.6175 | 0.207303
1453042 | PISO 5 | 1.6175 | 0.208653
1453044 | PISO 5 | 1.6175 | 0.208398
1453048 | PISO 5 | 1.6175 | 0.207303
1453050 | PISO 5 | 1.6175 | 0.207303
1453052 | PISO 5 | 1.6175 | 0.208653
1453054 | PISO 5 | 1.6175 | 0.208398
1453056 | PISO 5 | 1.6175 | 0.207303
1453058 | PISO 5 | 1.6175 | 0.207303
1453060 | PISO 5 | 1.6175 | 0.208653
1453062 | PISO 5 | 1.6175 | 0.208398
1453064 | PISO 5 | 1.6175 | 0.207303
1453066 | PISO 5 | 1.6175 | 0.207303
1453068 | PISO 5 | 1.584 | 0.2048
1453070 | PISO 5 | 1.6175 | 0.208398
1453460 | PISO 6 | 0.09 | 0.2502 | Qto_ColumnBaseQuantities - Length: 2.78 m; OuterSurfaceArea: 3.614 m2; GrossVolume: 0.2502 m3
1453462 | PISO 6 | 0.09 | 0.2115 | Qto_ColumnBaseQuantities - Length: 2.35 m; OuterSurfaceArea: 3.055 m2; GrossVolume: 0.2115 m3
1453466 | PISO 6 | 0.09 | 0.3015 | Qto_ColumnBaseQuantities - Length: 3.35 m; OuterSurfaceArea: 4.355 m2; GrossVolume: 0.3015 m3
1453468 | PISO 6 | 0.09 | 0.3015 | Qto_ColumnBaseQuantities - Length: 3.35 m; OuterSurfaceArea: 4.355 m2; GrossVolume: 0.3015 m3
1453470 | PISO 6 | 0.09 | 0.2115 | Qto_ColumnBaseQuantities - Length: 2.35 m; OuterSurfaceArea: 3.055 m2; GrossVolume: 0.2115 m3
1453474 | PISO 6 | 0.09 | 0.2502 | Qto_ColumnBaseQuantities - Length: 2.78 m; OuterSurfaceArea: 3.614 m2; GrossVolume: 0.2502 m3
1453476 | PISO 6 | 0.09 | 0.3015 | Qto_ColumnBaseQuantities - Length: 3.35 m; OuterSurfaceArea: 4.355 m2; GrossVolume: 0.3015 m3
1453478 | PISO 6 | 0.09 | 0.3015 | Qto_ColumnBaseQuantities - Length: 3.35 m; OuterSurfaceArea: 4.355 m2; GrossVolume: 0.3015 m3
1453480 | PISO 6 | 0.09 | 0.297 | Qto_ColumnBaseQuantities - Length: 3.3 m; OuterSurfaceArea: 4.29 m2; GrossVolume: 0.297 m3
1453482 | PISO 6 | 0.09 | 0.252 | Qto_ColumnBaseQuantities - Length: 2.8 m; OuterSurfaceArea: 3.64 m2; GrossVolume: 0.252 m3
1453484 | PISO 6 | 0.09 | 0.3015 | Qto_ColumnBaseQuantities - Length: 3.35 m; OuterSurfaceArea: 4.355 m2; GrossVolume: 0.3015 m3
1453486 | PISO 6 | 0.09 | 0.3015 | Qto_ColumnBaseQuantities - Length: 3.35 m; OuterSurfaceArea: 4.355 m2; GrossVolume: 0.3015 m3
1453488 | PISO 6 | 0.09 | 0.297 | Qto_ColumnBaseQuantities - Length: 3.3 m; OuterSurfaceArea: 4.29 m2; GrossVolume: 0.297 m3
1453490 | PISO 6 | 0.09 | 0.252 | Qto_ColumnBaseQuantities - Length: 2.8 m; OuterSurfaceArea: 3.64 m2; GrossVolume: 0.252 m3
1453492 | PISO 6 | 0.09 | 0.3015 | Qto_ColumnBaseQuantities - Length: 3.35 m; OuterSurfaceArea: 4.355 m2; GrossVolume: 0.3015 m3
1453494 | PISO 6 | 0.09 | 0.3015 | Qto_ColumnBaseQuantities - Length: 3.35 m; OuterSurfaceArea: 4.355 m2; GrossVolume: 0.3015 m3
1453496 | PISO 6 | 0.09 | 0.297 | Qto_ColumnBaseQuantities - Length: 3.3 m; OuterSurfaceArea: 4.29 m2; GrossVolume: 0.297 m3

# IfcOpeningElement (34)
PredefinedType: OPENING; Classification: 21.02.20.10.20 Uniformat (Uniformat)
Pset_EnvironmentalImpactIndicators - Reference: MURO 10cm; sets with these values: 2
Name (Basic Wall:MURO 10cm:...) | In | Height (m) | Width (m)
3 x 342347 | CIMENTACIÓN | 0.265113 | 0.776287
2 x 342347 | PISO 2 | 0.265113 | 0.776287
2 x 342347 | PISO 2 | 0.776287 | 0.265113
2 x 342347 | PISO 2 | 0.15 | 0.49
342347 | CIMENTACIÓN | 0.15 | 0.495
342347 | CIMENTACIÓN | 0.776287 | 0.265113
342347 | CIMENTACIÓN | 0.15 | 0.49
3 x 342347 | PISO 3 | 0.265113 | 0.776287
2 x 342347 | PISO 3 | 0.15 | 0.49
342347 | PISO 3 | 0.776287 | 0.265113
342347 | PISO 4 | 0.265113 | 0.776287
342347 | PISO 4 | 0.265112 | 0.776287
342347 | PISO 4 | 0.776287 | 0.265112
2 x 342347 | PISO 4 | 0.15 | 0.49
342347 | PISO 4 | 0.776287 | 0.265113
3 x 342347 | PISO 5 | 0.265113 | 0.776287
2 x 342347 | PISO 5 | 0.15 | 0.49
342347 | PISO 5 | 0.776287 | 0.265113
342347 | PISO 6 | 0.265112 | 0.776287
342347 | PISO 6 | 0.776287 | 0.265112
2 x 342347 | PISO 6 | 0.776287 | 0.265113

# IfcSlab: Floor:PLACA ESTRUCTURAL 0.10 (94)
Type - PredefinedType: FLOOR; Material: Concrete - Cast-in-Place Concrete - 28 MPa SLAB
Type - Pset_SlabCommon - IsExternal: no
Classification: 21.02.10.10.20 Uniformat (Uniformat)
Pset_EnvironmentalImpactIndicators - Reference: PLACA ESTRUCTURAL 0.10; sets with these values: 2
Pset_SlabCommon - Reference: PLACA ESTRUCTURAL 0.10; PitchAngle: 0 deg; LoadBearing: yes
Name (Floor:PLACA ESTRUCTURAL 0.10:...) | In | Perimeter (m) | GrossArea (m2) | NetVolume (m3)
370101 | PISO 2 | 39.5997 | 8.0133 | 0.80133 | Qto_SlabBaseQuantities - Depth: 0.1 m; GrossVolume: 0.80133 m3
702638 | PISO 2 | 65.7808 | 18.8859 | 1.88859 | Qto_SlabBaseQuantities - Depth: 0.1 m; GrossVolume: 1.88859 m3
702718 | PISO 2 | 39.5997 | 8.0133 | 0.80133 | Qto_SlabBaseQuantities - Depth: 0.1 m; GrossVolume: 0.80133 m3
703668 | PISO 2 | 65.7808 | 18.8859 | 1.88859 | Qto_SlabBaseQuantities - Depth: 0.1 m; GrossVolume: 1.88859 m3
703679 | PISO 2 | 39.5997 | 8.0133 | 0.80133 | Qto_SlabBaseQuantities - Depth: 0.1 m; GrossVolume: 0.80133 m3
703768 | PISO 2 | 39.5997 | 8.0133 | 0.80133 | Qto_SlabBaseQuantities - Depth: 0.1 m; GrossVolume: 0.80133 m3
713006 | PISO 3 | 39.5997 | 8.0133 | 0.80133 | Qto_SlabBaseQuantities - Depth: 0.1 m; GrossVolume: 0.80133 m3
713084 | PISO 3 | 65.7808 | 18.8859 | 1.88859 | Qto_SlabBaseQuantities - Depth: 0.1 m; GrossVolume: 1.88859 m3
713095 | PISO 3 | 39.5997 | 8.0133 | 0.80133 | Qto_SlabBaseQuantities - Depth: 0.1 m; GrossVolume: 0.80133 m3
713108 | PISO 3 | 498.819 | 6.26599 | 10.0057
713108:2 | PISO 3 | 498.819 | 5.3535 | 10.0057
713108:3 | PISO 3 | 498.819 | 5.3535 | 10.0057
713108:4 | PISO 3 | 498.819 | 5.4225 | 10.0057
713108:5 | PISO 3 | 498.819 | 5.4225 | 10.0057
713108:6 | PISO 3 | 498.819 | 22.2218 | 10.0057
713108:7 | PISO 3 | 498.819 | 22.2218 | 10.0057
713108:8 | PISO 3 | 498.819 | 5.4225 | 10.0057
713108:9 | PISO 3 | 498.819 | 5.4225 | 10.0057
713108:10 | PISO 3 | 498.819 | 6.26599 | 10.0057
713108:11 | PISO 3 | 498.819 | 5.342 | 10.0057
713108:12 | PISO 3 | 498.819 | 5.342 | 10.0057
713182 | PISO 3 | 65.7808 | 18.8859 | 1.88859 | Qto_SlabBaseQuantities - Depth: 0.1 m; GrossVolume: 1.88859 m3
713193 | PISO 3 | 39.5997 | 8.0133 | 0.80133 | Qto_SlabBaseQuantities - Depth: 0.1 m; GrossVolume: 0.80133 m3
713207 | PISO 3 | 39.5997 | 8.0133 | 0.80133 | Qto_SlabBaseQuantities - Depth: 0.1 m; GrossVolume: 0.80133 m3
718573 | PISO 4 | 39.5997 | 8.0133 | 0.80133 | Qto_SlabBaseQuantities - Depth: 0.1 m; GrossVolume: 0.80133 m3
718651 | PISO 4 | 65.7808 | 18.8859 | 1.88859 | Qto_SlabBaseQuantities - Depth: 0.1 m; GrossVolume: 1.88859 m3
718662 | PISO 4 | 39.5997 | 8.0133 | 0.80133 | Qto_SlabBaseQuantities - Depth: 0.1 m; GrossVolume: 0.80133 m3
718675 | PISO 4 | 498.819 | 6.26599 | 10.0061
718675:2 | PISO 4 | 498.819 | 5.3545 | 10.0061
718675:3 | PISO 4 | 498.819 | 5.3545 | 10.0061
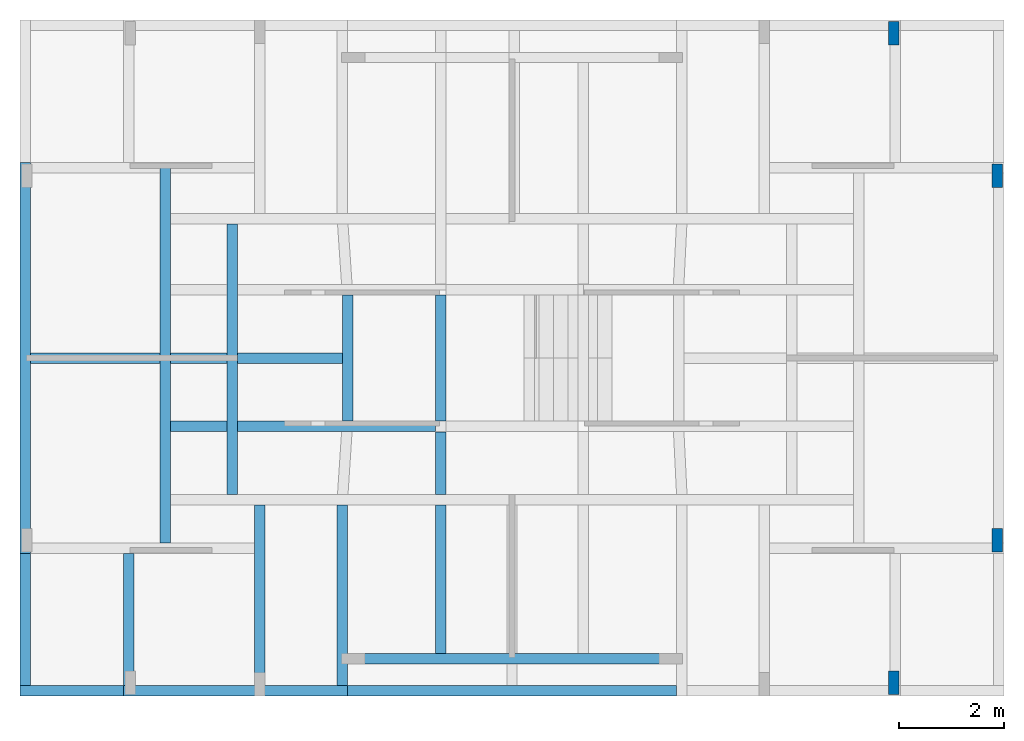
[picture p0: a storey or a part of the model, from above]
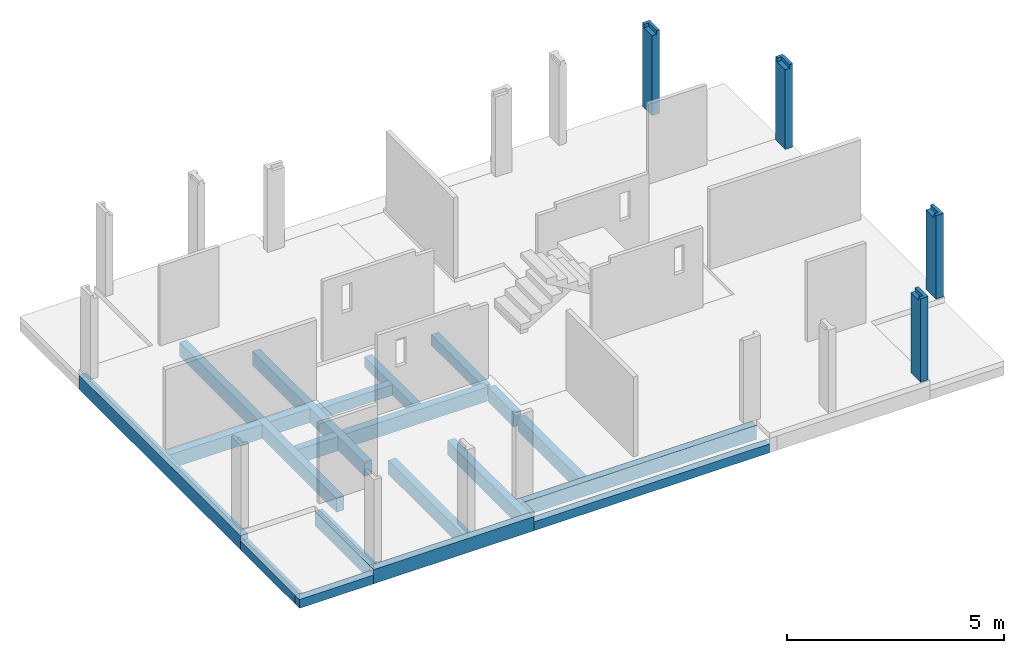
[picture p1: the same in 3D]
Properties of the parts of a building model (IFC4), part 2 of 2

# IfcSlab: Floor:PLACA ESTRUCTURAL 0.10 (94)
Name (Floor:PLACA ESTRUCTURAL 0.10:...) | In | Perimeter (m) | GrossArea (m2) | NetVolume (m3)
718675:4 | PISO 4 | 498.819 | 5.4225 | 10.0061
718675:5 | PISO 4 | 498.819 | 5.4225 | 10.0061
718675:6 | PISO 4 | 498.819 | 22.2218 | 10.0061
718675:7 | PISO 4 | 498.819 | 22.2218 | 10.0061
718675:8 | PISO 4 | 498.819 | 5.4225 | 10.0061
718675:9 | PISO 4 | 498.819 | 5.4225 | 10.0061
718675:10 | PISO 4 | 498.819 | 6.26599 | 10.0061
718675:11 | PISO 4 | 498.819 | 5.343 | 10.0061
718675:12 | PISO 4 | 498.819 | 5.343 | 10.0061
718749 | PISO 4 | 65.7808 | 18.8859 | 1.88859 | Qto_SlabBaseQuantities - Depth: 0.1 m; GrossVolume: 1.88859 m3
718760 | PISO 4 | 39.5997 | 8.0133 | 0.80133 | Qto_SlabBaseQuantities - Depth: 0.1 m; GrossVolume: 0.80133 m3
718774 | PISO 4 | 39.5997 | 8.0133 | 0.80133 | Qto_SlabBaseQuantities - Depth: 0.1 m; GrossVolume: 0.80133 m3
719014 | PISO 5 | 39.5997 | 8.0133 | 0.80133 | Qto_SlabBaseQuantities - Depth: 0.1 m; GrossVolume: 0.80133 m3
719092 | PISO 5 | 65.7808 | 18.8859 | 1.88859 | Qto_SlabBaseQuantities - Depth: 0.1 m; GrossVolume: 1.88859 m3
719103 | PISO 5 | 39.5997 | 8.0133 | 0.80133 | Qto_SlabBaseQuantities - Depth: 0.1 m; GrossVolume: 0.80133 m3
719116 | PISO 5 | 498.819 | 6.26599 | 10.0057
719116:2 | PISO 5 | 498.819 | 5.3535 | 10.0057
719116:3 | PISO 5 | 498.819 | 5.3535 | 10.0057
719116:4 | PISO 5 | 498.819 | 5.4225 | 10.0057
719116:5 | PISO 5 | 498.819 | 5.4225 | 10.0057
719116:6 | PISO 5 | 498.819 | 22.2218 | 10.0057
719116:7 | PISO 5 | 498.819 | 22.2218 | 10.0057
719116:8 | PISO 5 | 498.819 | 5.4225 | 10.0057
719116:9 | PISO 5 | 498.819 | 5.4225 | 10.0057
719116:10 | PISO 5 | 498.819 | 6.26599 | 10.0057
719116:11 | PISO 5 | 498.819 | 5.342 | 10.0057
719116:12 | PISO 5 | 498.819 | 5.342 | 10.0057
719190 | PISO 5 | 65.7808 | 18.8859 | 1.88859 | Qto_SlabBaseQuantities - Depth: 0.1 m; GrossVolume: 1.88859 m3
719201 | PISO 5 | 39.5997 | 8.0133 | 0.80133 | Qto_SlabBaseQuantities - Depth: 0.1 m; GrossVolume: 0.80133 m3
719215 | PISO 5 | 39.5997 | 8.0133 | 0.80133 | Qto_SlabBaseQuantities - Depth: 0.1 m; GrossVolume: 0.80133 m3
719431 | PISO 6 | 39.5997 | 8.0133 | 0.80133 | Qto_SlabBaseQuantities - Depth: 0.1 m; GrossVolume: 0.80133 m3
719509 | PISO 6 | 65.7808 | 18.8859 | 1.88859 | Qto_SlabBaseQuantities - Depth: 0.1 m; GrossVolume: 1.88859 m3
719520 | PISO 6 | 39.5997 | 8.0133 | 0.80133 | Qto_SlabBaseQuantities - Depth: 0.1 m; GrossVolume: 0.80133 m3
719533 | PISO 6 | 501.968 | 6.26599 | 10.1792
719533:2 | PISO 6 | 501.968 | 5.3535 | 10.1792
719533:3 | PISO 6 | 501.968 | 5.3535 | 10.1792
719533:4 | PISO 6 | 501.968 | 5.4225 | 10.1792
719533:5 | PISO 6 | 501.968 | 5.4225 | 10.1792
719533:6 | PISO 6 | 501.968 | 22.2218 | 10.1792
719533:7 | PISO 6 | 501.968 | 22.2218 | 10.1792
719533:8 | PISO 6 | 501.968 | 7.1577 | 10.1792
719533:9 | PISO 6 | 501.968 | 5.4225 | 10.1792
719533:10 | PISO 6 | 501.968 | 6.26599 | 10.1792
719533:11 | PISO 6 | 501.968 | 5.342 | 10.1792
719533:12 | PISO 6 | 501.968 | 5.342 | 10.1792
719607 | PISO 6 | 65.7808 | 18.8859 | 1.88859 | Qto_SlabBaseQuantities - Depth: 0.1 m; GrossVolume: 1.88859 m3
719618 | PISO 6 | 39.5997 | 8.0133 | 0.80133 | Qto_SlabBaseQuantities - Depth: 0.1 m; GrossVolume: 0.80133 m3
719632 | PISO 6 | 39.5997 | 8.0133 | 0.80133 | Qto_SlabBaseQuantities - Depth: 0.1 m; GrossVolume: 0.80133 m3
751977 | CUBIERTA | 34.6949 |  | 0.380985
751988 | CUBIERTA | 56.2336 | 10.008 | 1.0008 | Qto_SlabBaseQuantities - Depth: 0.1 m; GrossVolume: 1.0008 m3
752023 | CUBIERTA | 34.6949 |  | 0.385581
1035245 | PISO 2 | 543.668 | 6.26599 | 10.3741
1035245:2 | PISO 2 | 543.668 | 5.354 | 10.3741
1035245:3 | PISO 2 | 543.668 | 5.354 | 10.3741
1035245:4 | PISO 2 | 543.668 | 5.4225 | 10.3741
1035245:5 | PISO 2 | 543.668 | 5.4225 | 10.3741
1035245:6 | PISO 2 | 543.668 | 22.0418 | 10.3741
1035245:7 | PISO 2 | 543.668 | 22.2218 | 10.3741
1035245:8 | PISO 2 | 543.668 | 5.4225 | 10.3741
1035245:9 | PISO 2 | 543.668 | 5.4225 | 10.3741
1035245:10 | PISO 2 | 543.668 | 6.26599 | 10.3741
1035245:11 | PISO 2 | 543.668 | 5.3425 | 10.3741
1035245:12 | PISO 2 | 543.668 | 5.34295 | 10.3741
1035245:13 | PISO 2 | 543.668 | 3.8622 | 10.3741

# IfcSlab: Floor:PLACA ESTRUCTURAL 0.12 (5)
Type - PredefinedType: FLOOR; Material: Concrete, Cast In Situ
Type - Pset_SlabCommon - IsExternal: no; ThermalTransmittance: 8.71667 kg/K/s3
Classification: 21.02.10.10.20 Uniformat (Uniformat)
Pset_EnvironmentalImpactIndicators - Reference: PLACA ESTRUCTURAL 0.12; sets with these values: 2
Pset_SlabCommon - PitchAngle: 0 deg; LoadBearing: yes; Reference: PLACA ESTRUCTURAL 0.12
Qto_SlabBaseQuantities - Length: 2.4 m; Depth: 0.12 m
Name (Floor:PLACA ESTRUCTURAL 0.12:...) | In | Width (m) | Perimeter (m) | GrossArea (m2) | GrossVolume (m3) = NetVolume (m3)
1184935 | PISO 2 | 1.795 | 27.5262 | 4.308 | 0.51696
1186137 | PISO 3 | 1.575 | 26.0827 | 3.78 | 0.4536
1186320 | PISO 4 | 1.575 | 26.0827 | 3.78 | 0.4536
1186469 | PISO 5 | 1.575 | 26.0827 | 3.78 | 0.4536
1186641 | PISO 6 | 1.575 | 26.0827 | 3.78 | 0.4536

# IfcSlab: Floor:PLACA ESTRUCTURAL 0.15 (8)
In: CIMENTACIÓN
Type - PredefinedType: FLOOR; Material: Concrete - Cast-in-Place Concrete - 28 MPa SLAB
Type - Pset_SlabCommon - IsExternal: no
Classification: 21.01.40.10.10 Uniformat (Uniformat)
Pset_EnvironmentalImpactIndicators - Reference: PLACA ESTRUCTURAL 0.15; sets with these values: 2
Pset_SlabCommon - PitchAngle: 0 deg; LoadBearing: yes; Reference: PLACA ESTRUCTURAL 0.15
Name (Floor:PLACA ESTRUCTURAL 0.15:...) | Perimeter (m) | GrossArea (m2) | NetVolume (m3)
410710 | 124.016 | 36.0039 | 5.40059 | Qto_SlabBaseQuantities - Depth: 0.15 m; GrossVolume: 5.40059 m3
598789 | 213.586 | 5.36212 | 4.37608
598789:2 | 213.586 | 5.36212 | 4.37608
598789:3 | 213.586 | 5.36259 | 4.37608
598789:4 | 213.586 | 3.8622 | 4.37608
598789:5 | 213.586 | 3.8622 | 4.37608
598789:6 | 213.586 | 5.36259 | 4.37608
868729 | 331.89 | 176.64 | 26.4959 | Qto_SlabBaseQuantities - Depth: 0.15 m; GrossVolume: 26.4959 m3

# IfcSlab: Monolithic Landing:120mm Thickness (5)
Type - PredefinedType: LANDING
Type - Pset_SlabCommon - IsExternal: no
Classification: 21.02.10.80.10 Uniformat (Uniformat); Material: Concrete, Cast-in-Place gray
Pset_EnvironmentalImpactIndicators - Reference: 120mm Thickness; sets with these values: 2
Pset_SlabCommon - PitchAngle: 0 deg; Reference: 120mm Thickness
Qto_SlabBaseQuantities - NetVolume: 0.383767 m3
Name (Cast-In-Place Stair:Stair:...) | In
523479 Landing 1 | CIMENTACIÓN
524135 Landing 1 | PISO 2
524154 Landing 1 | PISO 3
524173 Landing 1 | PISO 4
524192 Landing 1 | PISO 5

# IfcStair: Cast-In-Place Stair:B1080_Escalera Monolitica en Concreto (5)
Type - PredefinedType: HALF_TURN_STAIR
Type - Pset_StairCommon - IsExternal: no; NosingLength: 0 m; NumberOfRiser: 0; NumberOfTreads: 0
Type - Pset_StairFlightCommon - NosingLength: 0 m; NumberOfRiser: 0; NumberOfTreads: 0
Classification: 21.02.10.80.10 Uniformat (Uniformat)
Pset_EnvironmentalImpactIndicators - Reference: B1080_Escalera Monolitica en Concreto
Pset_StairCommon - Reference: B1080_Escalera Monolitica en Concreto; NumberOfRiser: 14; NumberOfTreads: 12; RiserHeight: 0.167857 m; TreadLength: 0.28 m; TreadLengthAtOffset: 0.28 m; TreadLengthAtInnerSide: 0.28 m
Pset_StairFlightCommon - Reference: B1080_Escalera Monolitica en Concreto; NumberOfRiser: 14; NumberOfTreads: 12; RiserHeight: 0.167857 m; TreadLength: 0.28 m; TreadLengthAtOffset: 0.28 m; TreadLengthAtInnerSide: 0.28 m
Name (Cast-In-Place Stair:Stair:...) | In | Pset_StairCommon, WalkingLineOffset (m) = Pset_StairFlightCommon, WalkingLineOffset (m)
523479 | CIMENTACIÓN
524135 | PISO 2 | 1.9685
524154 | PISO 3 | 1.9685
524173 | PISO 4 | 1.9685
524192 | PISO 5 | 1.9685

# IfcStair: GTHBHB:GTHBHB, GTHBHB:GTHBHB:877879
In: CIMENTACIÓN
Type - Pset_StairCommon - IsExternal: no; NosingLength: 0 m; NumberOfRiser: 0; NumberOfTreads: 0
Type - Pset_StairFlightCommon - NosingLength: 0 m; NumberOfRiser: 0; NumberOfTreads: 0
Classification: 21.02.10.80.10 Uniformat (Uniformat); Material: Concrete, Cast-in-Place gray
Pset_EnvironmentalImpactIndicators - Reference: GTHBHB; sets with these values: 2
Pset_StairCommon - Reference: GTHBHB

# IfcStairFlight: Monolithic Run:120mm Depth (9)
Type - PredefinedType: STRAIGHT
Type - Pset_StairFlightCommon - NosingLength: 0 m
Classification: 21.02.10.80.10 Uniformat (Uniformat); Material: Concrete, Cast In Situ
Pset_EnvironmentalImpactIndicators - Reference: 120mm Depth
Pset_StairFlightCommon - Reference: 120mm Depth; NumberOfRiser: 7; NumberOfTreads: 6; RiserHeight: 0.167857 m; TreadLength: 0.28 m; TreadLengthAtOffset: 0.28 m; TreadLengthAtInnerSide: 0.28 m
Qto_StairFlightBaseQuantities - Length: 1.68 m
Name (Cast-In-Place Stair:Stair:...) | In | WalkingLineOffset (m) | NetVolume (m3)
523479 Run 2 | CIMENTACIÓN | 1.96686 | 0.450489
524135 Run 1 | PISO 2 | 1.9685 | 0.431669
524135 Run 2 | PISO 2 | 1.96686 | 0.450489
524154 Run 1 | PISO 3 | 1.9685 | 0.431669
524154 Run 2 | PISO 3 | 1.96686 | 0.450489
524173 Run 1 | PISO 4 | 1.9685 | 0.431669
524173 Run 2 | PISO 4 | 1.96686 | 0.450489
524192 Run 1 | PISO 5 | 1.9685 | 0.431669
524192 Run 2 | PISO 5 | 1.96686 | 0.450489

# IfcStairFlight: Monolithic Run:120mm Depth, Cast-In-Place Stair:Stair:523479 Run 1
In: CIMENTACIÓN
Type - Pset_StairFlightCommon - NosingLength: 0 m
Classification: 21.02.10.80.10 Uniformat (Uniformat); Material: Concrete, Cast In Situ
Pset_EnvironmentalImpactIndicators - Reference: 120mm Depth
Pset_StairFlightCommon - Reference: 120mm Depth; NumberOfRiser: 7; NumberOfTreads: 6; RiserHeight: 0.167857 m; TreadLength: 0.28 m; TreadLengthAtOffset: 0.28 m; TreadLengthAtInnerSide: 0.28 m
Qto_StairFlightBaseQuantities - Length: 1.68 m; NetVolume: 0.431669 m3

# IfcWall: Basic Wall:MURO .085cm (20)
Type - PredefinedType: STANDARD
Type - Pset_WallCommon - IsExternal: yes
Classification: 21.03.10.10.10 Uniformat (Uniformat); Material: Concrete - Cast-in-Place Concrete - 28 MPa SLAB
Qto_WallBaseQuantities - Height: 0.35 m; Length: 2.125 m; Width: 0.085 m; GrossFootprintArea: 0.180625 m2; GrossVolume: 0.0632188 m3; GrossSideArea: 0.74375 m2; NetSideArea: 0.74375 m2; NetVolume: 0.0632188 m3
Pset_EnvironmentalImpactIndicators - Reference: MURO .085cm; sets with these values: 2
Pset_WallCommon - LoadBearing: yes; ExtendToStructure: no; Reference: MURO .085cm
Name (Basic Wall:MURO .085cm:...) | In
1163097 | PISO 2
1163274 | PISO 3
1163278 | PISO 4
1163282 | PISO 5
1163331 | PISO 6
1163396 | PISO 4
1163471 | PISO 6
1163475 | PISO 2
1163479 | PISO 3
1163483 | PISO 5
1163571 | PISO 4
1163636 | PISO 4
1164647 | PISO 6
1164655 | PISO 2
1164659 | PISO 3
1164667 | PISO 5
1164768 | PISO 6
1164772 | PISO 2
1164776 | PISO 3
1164780 | PISO 5

# IfcWall: Basic Wall:MURO 10cm (52)
Type - PredefinedType: STANDARD
Type - Pset_WallCommon - IsExternal: yes
Classification: 21.02.20.10.20 Uniformat (Uniformat); Material: Concrete - Cast-in-Place Concrete - 35 MPa
Qto_WallBaseQuantities - Width: 0.1 m
Pset_EnvironmentalImpactIndicators - Reference: MURO 10cm; sets with these values: 2
Pset_WallCommon - LoadBearing: yes; ExtendToStructure: no; Reference: MURO 10cm
Name (Basic Wall:MURO 10cm:...) | In | Height (m) | Length (m) | GrossFootprintArea (m2) | GrossVolume (m3) | GrossSideArea (m2) | NetSideArea (m2) | NetVolume (m3)
376891 | CIMENTACIÓN | 2.25 | 1.56 | 0.156 | 0.351 | 3.51 | 3.51 | 0.351
377043 | CIMENTACIÓN | 2.25 | 1.56 | 0.156 | 0.351 | 3.51 | 3.51 | 0.351
377172 | CIMENTACIÓN | 2.25 | 1.56 | 0.156 | 0.351 | 3.51 | 3.51 | 0.351
377387 | CIMENTACIÓN | 2.25 | 1.56 | 0.156 | 0.351 | 3.51 | 3.51 | 0.351
387157 | CIMENTACIÓN | 2.25 | 2.95503 | 0.295503 | 0.657456 | 6.57456 | 6.36876 | 0.636876
502899 | PISO 2 | 2.25 | 1.56 | 0.156 | 0.351 | 3.51 | 3.51 | 0.351
502901 | PISO 2 | 2.25 | 1.56 | 0.156 | 0.351 | 3.51 | 3.51 | 0.351
502903 | PISO 2 | 2.25 | 1.56 | 0.156 | 0.351 | 3.51 | 3.51 | 0.351
502983 | PISO 2 | 2.25 | 2.955 | 0.2955 | 0.664875 | 6.64875 | 6.44295 | 0.644295
512880 | PISO 2 | 2.25 | 1.56 | 0.156 | 0.351 | 3.51 | 3.51 | 0.351
538417 | PISO 2 | 2.25 | 2.955 | 0.2955 | 0.664875 | 6.64875 | 6.44295 | 0.644295
538551 | CIMENTACIÓN | 2.25 | 2.955 | 0.2955 | 0.65745 | 6.5745 | 6.3687 | 0.63687
539606 | PISO 2 | 2.25 | 2.955 | 0.2955 | 0.657525 | 6.57525 | 6.36945 | 0.636945
539694 | CIMENTACIÓN | 2.25 | 2.955 | 0.2955 | 0.65745 | 6.5745 | 6.3687 | 0.63687
541679 | PISO 2 | 2.25 | 2.955 | 0.2955 | 0.657525 | 6.57525 | 6.36945 | 0.636945
541924 | CIMENTACIÓN | 2.25 | 2.955 | 0.2955 | 0.0225 | 0.225 | 6.36937 | 0.636937
552582 | PISO 3 | 2.25 | 1.56 | 0.156 | 0.351 | 3.51 | 3.51 | 0.351
552584 | PISO 3 | 2.25 | 1.56 | 0.156 | 0.351 | 3.51 | 3.51 | 0.351
552586 | PISO 3 | 2.25 | 1.56 | 0.156 | 0.351 | 3.51 | 3.51 | 0.351
552650 | PISO 3 | 2.25 | 2.955 | 0.2955 | 0.664875 | 6.64875 | 6.44295 | 0.644295
553142 | PISO 3 | 2.25 | 1.56 | 0.156 | 0.351 | 3.51 | 3.51 | 0.351
553146 | PISO 3 | 2.25 | 2.955 | 0.2955 | 0.664875 | 6.64875 | 6.44295 | 0.644295
553165 | PISO 3 | 2.25 | 2.955 | 0.2955 | 0.657525 | 6.57525 | 6.36945 | 0.636945
553189 | PISO 3 | 2.25 | 2.955 | 0.2955 | 0.657525 | 6.57525 | 6.36945 | 0.636945
555085 | PISO 4 | 2.25 | 1.56 | 0.156 | 0.351 | 3.51 | 3.51 | 0.351
555087 | PISO 4 | 2.25 | 1.56 | 0.156 | 0.351 | 3.51 | 3.51 | 0.351
555089 | PISO 4 | 2.25 | 1.56 | 0.156 | 0.351 | 3.51 | 3.51 | 0.351
555153 | PISO 4 | 2.25 | 2.955 | 0.2955 | 0.664875 | 6.64875 | 6.44295 | 0.644295
555645 | PISO 4 | 2.25 | 1.56 | 0.156 | 0.351 | 3.51 | 3.51 | 0.351
555649 | PISO 4 | 2.25 | 2.955 | 0.2955 | 0.664875 | 6.64875 | 6.44295 | 0.644295
555668 | PISO 4 | 2.25 | 2.955 | 0.2955 | 0.657525 | 6.57525 | 6.36945 | 0.636945
555692 | PISO 4 | 2.25 | 2.955 | 0.2955 | 0.657525 | 6.57525 | 6.36945 | 0.636945
556056 | PISO 5 | 2.25 | 1.56 | 0.156 | 0.351 | 3.51 | 3.51 | 0.351
556058 | PISO 5 | 2.25 | 1.56 | 0.156 | 0.351 | 3.51 | 3.51 | 0.351
556060 | PISO 5 | 2.25 | 1.56 | 0.156 | 0.351 | 3.51 | 3.51 | 0.351
556124 | PISO 5 | 2.25 | 2.955 | 0.2955 | 0.664875 | 6.64875 | 6.44295 | 0.644295
556616 | PISO 5 | 2.25 | 1.56 | 0.156 | 0.351 | 3.51 | 3.51 | 0.351
556620 | PISO 5 | 2.25 | 2.955 | 0.2955 | 0.664875 | 6.64875 | 6.44295 | 0.644295
556639 | PISO 5 | 2.25 | 2.955 | 0.2955 | 0.657525 | 6.57525 | 6.36945 | 0.636945
556663 | PISO 5 | 2.25 | 2.955 | 0.2955 | 0.657525 | 6.57525 | 6.36945 | 0.636945
557027 | PISO 6 | 2.35 | 1.56 | 0.156 | 0.3666 | 3.666 | 3.666 | 0.3666
557591 | PISO 6 | 2.4161 | 2.955 | 0.2955 | 0.713958 | 7.13958 | 6.93377 | 0.693377
751779 | CUBIERTA | 0.4284 | 1.6275 | 0.16275 | 0.0697221 | 0.697221 | 0.697221 | 0.0697221
813567 | PISO 6 | 2.35 | 1.56 | 0.156 | 0.3666 | 3.666 | 3.666 | 0.3666
813622 | CUBIERTA | 0.4284 | 1.6275 | 0.16275 | 0.0697221 | 0.697221 | 0.697221 | 0.0697221
813997 | PISO 6 | 2.35 | 1.56 | 0.156 | 0.3666 | 3.666 | 3.666 | 0.3666
814052 | CUBIERTA | 0.4284 | 1.6275 | 0.16275 | 0.0697221 | 0.697221 | 0.697221 | 0.0697221
814390 | PISO 6 | 2.35 | 1.56 | 0.156 | 0.3666 | 3.666 | 3.666 | 0.3666
814445 | CUBIERTA | 0.4284 | 1.6275 | 0.16275 | 0.0697221 | 0.697221 | 0.697221 | 0.0697221
819748 | PISO 6 | 2.4161 | 2.955 | 0.2955 | 0.713958 | 7.13958 | 6.93377 | 0.693377
819818 | PISO 6 | 2.4161 | 2.955 | 0.2955 | 0.683155 | 6.83155 | 6.62575 | 0.66257
819907 | PISO 6 | 2.4161 | 2.955 | 0.2955 | 0.684119 | 6.84119 | 6.63539 | 0.663539

# IfcWall: Basic Wall:MURO 12cm (24)
Type - PredefinedType: STANDARD
Type - Pset_WallCommon - IsExternal: yes
Classification: 21.03.10.10.10 Uniformat (Uniformat); Material: Concrete - Cast-in-Place Concrete - 35 MPa
Qto_WallBaseQuantities - Width: 0.12 m
Pset_EnvironmentalImpactIndicators - Reference: MURO 12cm; sets with these values: 2
Pset_WallCommon - LoadBearing: yes; Reference: MURO 12cm; ExtendToStructure: no
Name (Basic Wall:MURO 12cm:...) | In | Height (m) | Length (m) | GrossFootprintArea (m2) | GrossVolume (m3) = NetVolume (m3) | GrossSideArea (m2) = NetSideArea (m2)
375683 | CIMENTACIÓN | 2.25 | 3.105 | 0.3726 | 0.83835 | 6.98625
375919 | CIMENTACIÓN | 2.25 | 3.105 | 0.3726 | 0.83835 | 6.98625
492206 | CIMENTACIÓN | 2.25 | 4.02 | 0.4824 | 1.0854 | 9.045
502893 | PISO 2 | 2.25 | 3.105 | 0.3726 | 0.83835 | 6.98625
502895 | PISO 2 | 2.25 | 3.105 | 0.3726 | 0.83835 | 6.98625
503437 | PISO 2 | 2.25 | 4.02 | 0.4824 | 1.0854 | 9.045
511923 | CIMENTACIÓN | 2.25 | 4.02 | 0.4824 | 1.0854 | 9.045
512481 | PISO 2 | 2.25 | 4.02 | 0.4824 | 1.0854 | 9.045
552578 | PISO 3 | 2.25 | 3.105 | 0.3726 | 0.83835 | 6.98625
552580 | PISO 3 | 2.25 | 3.105 | 0.3726 | 0.83835 | 6.98625
553008 | PISO 3 | 2.25 | 4.02 | 0.4824 | 1.0854 | 9.045
553136 | PISO 3 | 2.25 | 4.02 | 0.4824 | 1.0854 | 9.045
555081 | PISO 4 | 2.25 | 3.105 | 0.3726 | 0.83835 | 6.98625
555083 | PISO 4 | 2.25 | 3.105 | 0.3726 | 0.83835 | 6.98625
555511 | PISO 4 | 2.25 | 4.02 | 0.4824 | 1.0854 | 9.045
555639 | PISO 4 | 2.25 | 4.02 | 0.4824 | 1.0854 | 9.045
556052 | PISO 5 | 2.25 | 3.105 | 0.3726 | 0.83835 | 6.98625
556054 | PISO 5 | 2.25 | 3.105 | 0.3726 | 0.83835 | 6.98625
556482 | PISO 5 | 2.25 | 4.02 | 0.4824 | 1.0854 | 9.045
556610 | PISO 5 | 2.25 | 4.02 | 0.4824 | 1.0854 | 9.045
557023 | PISO 6 | 3.08964 | 3.105 | 0.3726 | 1.0645 | 8.87087
557581 | PISO 6 | 2.25 | 4.02 | 0.4824 | 1.08538 | 9.04485
813565 | PISO 6 | 3.08964 | 3.105 | 0.3726 | 1.06434 | 8.86952
821075 | PISO 6 | 2.25 | 4.02 | 0.4824 | 1.08538 | 9.04485
